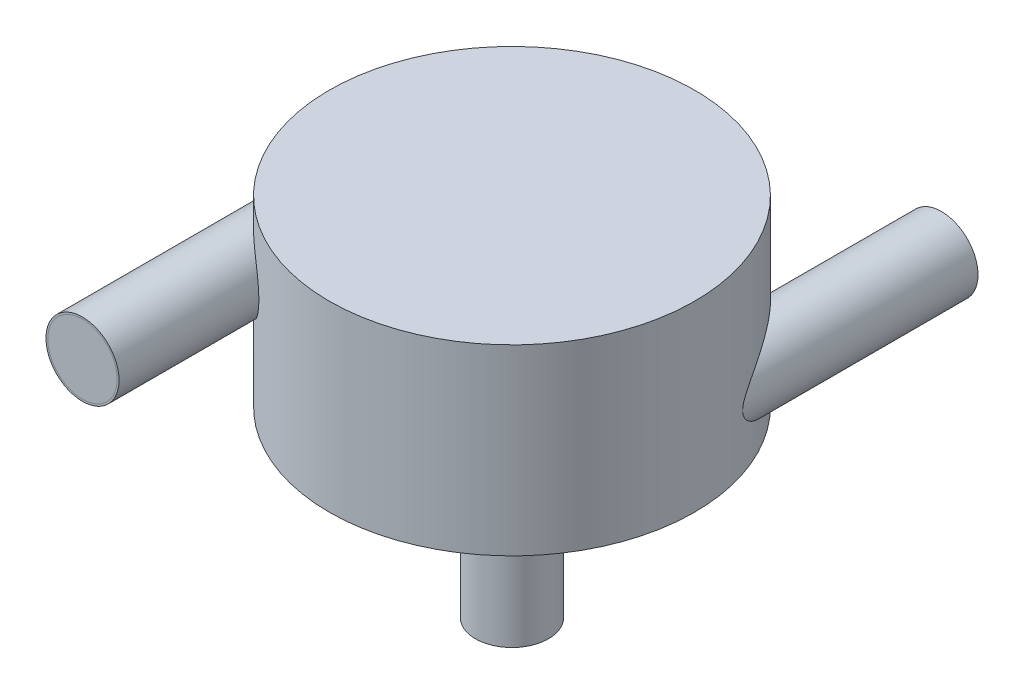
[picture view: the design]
ISO-10303-21;
HEADER;
FILE_DESCRIPTION(('STEP AP214'),'2;1');
FILE_NAME('part.step','',(''),(''),'','','');
FILE_SCHEMA(('AUTOMOTIVE_DESIGN { 1 0 10303 214 1 1 1 1 }'));
ENDSEC;
DATA;
#1=APPLICATION_CONTEXT('core data for automotive mechanical design processes');
#2=APPLICATION_PROTOCOL_DEFINITION('international standard','automotive_design',2000,#1);
#3=PRODUCT_CONTEXT('',#1,'mechanical');
#4=PRODUCT('Part','Part','',(#3));
#5=PRODUCT_RELATED_PRODUCT_CATEGORY('part','',(#4));
#6=PRODUCT_DEFINITION_FORMATION('','',#4);
#7=PRODUCT_DEFINITION_CONTEXT('part definition',#1,'design');
#8=PRODUCT_DEFINITION('design','',#6,#7);
#9=PRODUCT_DEFINITION_SHAPE('','',#8);
#10=(LENGTH_UNIT() NAMED_UNIT(*) SI_UNIT(.MILLI.,.METRE.));
#11=(NAMED_UNIT(*) PLANE_ANGLE_UNIT() SI_UNIT($,.RADIAN.));
#12=(NAMED_UNIT(*) SI_UNIT($,.STERADIAN.) SOLID_ANGLE_UNIT());
#13=UNCERTAINTY_MEASURE_WITH_UNIT(LENGTH_MEASURE(1.E-05),#10,'distance_accuracy_value','');
#14=(GEOMETRIC_REPRESENTATION_CONTEXT(3) GLOBAL_UNCERTAINTY_ASSIGNED_CONTEXT((#13)) GLOBAL_UNIT_ASSIGNED_CONTEXT((#10,
#11,#12)) REPRESENTATION_CONTEXT('',''));
#15=CARTESIAN_POINT('',(0.,0.,0.));
#16=DIRECTION('',(0.,0.,1.));
#17=DIRECTION('',(1.,0.,0.));
#18=AXIS2_PLACEMENT_3D('',#15,#16,#17);
#19=CARTESIAN_POINT('',(0.,-950.,0.));
#20=DIRECTION('',(0.,-1.,0.));
#21=DIRECTION('',(0.,0.,-1.));
#22=AXIS2_PLACEMENT_3D('',#19,#20,#21);
#23=CYLINDRICAL_SURFACE('',#22,190.);
#24=CARTESIAN_POINT('',(0.,-950.,0.));
#25=DIRECTION('',(0.,-1.,0.));
#26=DIRECTION('',(0.,0.,-1.));
#27=AXIS2_PLACEMENT_3D('',#24,#25,#26);
#28=CIRCLE('',#27,190.);
#29=CARTESIAN_POINT('',(0.,-950.,-190.));
#30=VERTEX_POINT('',#29);
#31=EDGE_CURVE('E11',#30,#30,#28,.T.);
#32=ORIENTED_EDGE('',*,*,#31,.T.);
#33=EDGE_LOOP('',(#32));
#34=FACE_BOUND('',#33,.T.);
#35=CARTESIAN_POINT('',(0.,-1000.,0.));
#36=DIRECTION('',(0.,-1.,0.));
#37=DIRECTION('',(0.,0.,-1.));
#38=AXIS2_PLACEMENT_3D('',#35,#36,#37);
#39=CIRCLE('',#38,190.);
#40=CARTESIAN_POINT('',(0.,-1000.,-190.));
#41=VERTEX_POINT('',#40);
#42=EDGE_CURVE('E63',#41,#41,#39,.T.);
#43=ORIENTED_EDGE('',*,*,#42,.F.);
#44=EDGE_LOOP('',(#43));
#45=FACE_BOUND('',#44,.T.);
#46=ADVANCED_FACE('F60',(#34,#45),#23,.T.);
#47=CARTESIAN_POINT('',(0.,-950.,0.));
#48=DIRECTION('',(0.,-1.,0.));
#49=DIRECTION('',(0.,0.,-1.));
#50=AXIS2_PLACEMENT_3D('',#47,#48,#49);
#51=PLANE('',#50);
#52=ORIENTED_EDGE('',*,*,#31,.F.);
#53=EDGE_LOOP('',(#52));
#54=FACE_BOUND('',#53,.T.);
#55=ADVANCED_FACE('F75',(#54),#51,.F.);
#56=CARTESIAN_POINT('',(0.,-1000.,0.));
#57=DIRECTION('',(0.,-1.,0.));
#58=DIRECTION('',(0.,0.,-1.));
#59=AXIS2_PLACEMENT_3D('',#56,#57,#58);
#60=PLANE('',#59);
#61=ORIENTED_EDGE('',*,*,#42,.T.);
#62=EDGE_LOOP('',(#61));
#63=FACE_BOUND('',#62,.T.);
#64=ADVANCED_FACE('F72',(#63),#60,.T.);
#65=CLOSED_SHELL('',(#46,#55,#64));
#66=MANIFOLD_SOLID_BREP('B2',#65);
#67=CARTESIAN_POINT('',(750.,300.,-1550.));
#68=DIRECTION('',(0.,0.,-1.));
#69=DIRECTION('',(-1.,0.,0.));
#70=AXIS2_PLACEMENT_3D('',#67,#68,#69);
#71=CYLINDRICAL_SURFACE('',#70,190.);
#72=CARTESIAN_POINT('',(750.,300.,-1550.));
#73=DIRECTION('',(0.,0.,-1.));
#74=DIRECTION('',(-1.,0.,0.));
#75=AXIS2_PLACEMENT_3D('',#72,#73,#74);
#76=CIRCLE('',#75,190.);
#77=CARTESIAN_POINT('',(560.,300.,-1550.));
#78=VERTEX_POINT('',#77);
#79=EDGE_CURVE('E59',#78,#78,#76,.T.);
#80=ORIENTED_EDGE('',*,*,#79,.T.);
#81=EDGE_LOOP('',(#80));
#82=FACE_BOUND('',#81,.T.);
#83=CARTESIAN_POINT('',(750.,300.,-1600.));
#84=DIRECTION('',(0.,0.,-1.));
#85=DIRECTION('',(-1.,0.,0.));
#86=AXIS2_PLACEMENT_3D('',#83,#84,#85);
#87=CIRCLE('',#86,190.);
#88=CARTESIAN_POINT('',(560.,300.,-1600.));
#89=VERTEX_POINT('',#88);
#90=EDGE_CURVE('E110',#89,#89,#87,.T.);
#91=ORIENTED_EDGE('',*,*,#90,.F.);
#92=EDGE_LOOP('',(#91));
#93=FACE_BOUND('',#92,.T.);
#94=ADVANCED_FACE('F107',(#82,#93),#71,.T.);
#95=CARTESIAN_POINT('',(750.,300.,-1550.));
#96=DIRECTION('',(0.,0.,-1.));
#97=DIRECTION('',(-1.,0.,0.));
#98=AXIS2_PLACEMENT_3D('',#95,#96,#97);
#99=PLANE('',#98);
#100=ORIENTED_EDGE('',*,*,#79,.F.);
#101=EDGE_LOOP('',(#100));
#102=FACE_BOUND('',#101,.T.);
#103=ADVANCED_FACE('F122',(#102),#99,.F.);
#104=CARTESIAN_POINT('',(750.,300.,-1600.));
#105=DIRECTION('',(0.,0.,-1.));
#106=DIRECTION('',(-1.,0.,0.));
#107=AXIS2_PLACEMENT_3D('',#104,#105,#106);
#108=PLANE('',#107);
#109=ORIENTED_EDGE('',*,*,#90,.T.);
#110=EDGE_LOOP('',(#109));
#111=FACE_BOUND('',#110,.T.);
#112=ADVANCED_FACE('F119',(#111),#108,.T.);
#113=CLOSED_SHELL('',(#94,#103,#112));
#114=MANIFOLD_SOLID_BREP('B6',#113);
#115=CARTESIAN_POINT('',(-750.,650.,1550.));
#116=DIRECTION('',(0.,0.,1.));
#117=DIRECTION('',(1.,0.,0.));
#118=AXIS2_PLACEMENT_3D('',#115,#116,#117);
#119=CYLINDRICAL_SURFACE('',#118,190.);
#120=CARTESIAN_POINT('',(-750.,650.,1550.));
#121=DIRECTION('',(0.,0.,1.));
#122=DIRECTION('',(1.,0.,0.));
#123=AXIS2_PLACEMENT_3D('',#120,#121,#122);
#124=CIRCLE('',#123,190.);
#125=CARTESIAN_POINT('',(-560.,650.,1550.));
#126=VERTEX_POINT('',#125);
#127=EDGE_CURVE('E106',#126,#126,#124,.T.);
#128=ORIENTED_EDGE('',*,*,#127,.T.);
#129=EDGE_LOOP('',(#128));
#130=FACE_BOUND('',#129,.T.);
#131=CARTESIAN_POINT('',(-750.,650.,1600.));
#132=DIRECTION('',(0.,0.,1.));
#133=DIRECTION('',(1.,0.,0.));
#134=AXIS2_PLACEMENT_3D('',#131,#132,#133);
#135=CIRCLE('',#134,190.);
#136=CARTESIAN_POINT('',(-560.,650.,1600.));
#137=VERTEX_POINT('',#136);
#138=EDGE_CURVE('E156',#137,#137,#135,.T.);
#139=ORIENTED_EDGE('',*,*,#138,.F.);
#140=EDGE_LOOP('',(#139));
#141=FACE_BOUND('',#140,.T.);
#142=ADVANCED_FACE('F153',(#130,#141),#119,.T.);
#143=CARTESIAN_POINT('',(-750.,650.,1550.));
#144=DIRECTION('',(0.,0.,1.));
#145=DIRECTION('',(1.,0.,0.));
#146=AXIS2_PLACEMENT_3D('',#143,#144,#145);
#147=PLANE('',#146);
#148=ORIENTED_EDGE('',*,*,#127,.F.);
#149=EDGE_LOOP('',(#148));
#150=FACE_BOUND('',#149,.T.);
#151=ADVANCED_FACE('F168',(#150),#147,.F.);
#152=CARTESIAN_POINT('',(-750.,650.,1600.));
#153=DIRECTION('',(0.,0.,1.));
#154=DIRECTION('',(1.,0.,0.));
#155=AXIS2_PLACEMENT_3D('',#152,#153,#154);
#156=PLANE('',#155);
#157=ORIENTED_EDGE('',*,*,#138,.T.);
#158=EDGE_LOOP('',(#157));
#159=FACE_BOUND('',#158,.T.);
#160=ADVANCED_FACE('F165',(#159),#156,.T.);
#161=CLOSED_SHELL('',(#142,#151,#160));
#162=MANIFOLD_SOLID_BREP('B54',#161);
#163=CARTESIAN_POINT('',(0.,1000.,0.));
#164=DIRECTION('',(0.,-1.,0.));
#165=DIRECTION('',(0.,0.,-1.));
#166=AXIS2_PLACEMENT_3D('',#163,#164,#165);
#167=CYLINDRICAL_SURFACE('',#166,1000.);
#168=CARTESIAN_POINT('',(-550.,650.,835.164654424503));
#169=CARTESIAN_POINT('',(-549.999999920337,652.438202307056,835.164654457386));
#170=CARTESIAN_POINT('',(-550.044599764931,654.876402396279,835.135288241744));
#171=CARTESIAN_POINT('',(-550.222835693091,659.748126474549,835.017869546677));
#172=CARTESIAN_POINT('',(-550.356471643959,662.181650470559,834.929817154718));
#173=CARTESIAN_POINT('',(-550.712289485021,667.039346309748,834.695165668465));
#174=CARTESIAN_POINT('',(-550.934470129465,669.463518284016,834.548567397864));
#175=CARTESIAN_POINT('',(-551.466569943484,674.297960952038,834.197053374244));
#176=CARTESIAN_POINT('',(-551.776489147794,676.708231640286,833.992137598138));
#177=CARTESIAN_POINT('',(-552.482958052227,681.510449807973,833.524301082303));
#178=CARTESIAN_POINT('',(-552.879510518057,683.902396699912,833.261378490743));
#179=CARTESIAN_POINT('',(-553.757820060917,688.663506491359,832.677941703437));
#180=CARTESIAN_POINT('',(-554.239577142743,691.032669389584,832.357427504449));
#181=CARTESIAN_POINT('',(-555.286588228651,695.743966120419,831.659305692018));
#182=CARTESIAN_POINT('',(-555.851842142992,698.086099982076,831.281698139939));
#183=CARTESIAN_POINT('',(-557.063869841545,702.739263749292,830.469973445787));
#184=CARTESIAN_POINT('',(-557.710643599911,705.050293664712,830.03585632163));
#185=CARTESIAN_POINT('',(-559.081828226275,709.631833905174,829.112893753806));
#186=CARTESIAN_POINT('',(-559.806048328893,711.902428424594,828.624182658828));
#187=CARTESIAN_POINT('',(-561.330956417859,716.40513498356,827.591931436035));
#188=CARTESIAN_POINT('',(-562.131644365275,718.637247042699,827.048391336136));
#189=CARTESIAN_POINT('',(-563.806827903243,723.059518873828,825.907311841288));
#190=CARTESIAN_POINT('',(-564.681322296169,725.249679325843,825.309773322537));
#191=CARTESIAN_POINT('',(-566.50130203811,729.584888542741,824.061582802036));
#192=CARTESIAN_POINT('',(-567.44678743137,731.729937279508,823.410930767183));
#193=CARTESIAN_POINT('',(-569.405774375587,735.971995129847,822.057468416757));
#194=CARTESIAN_POINT('',(-570.419276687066,738.069003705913,821.354657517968));
#195=CARTESIAN_POINT('',(-572.511169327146,742.212258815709,819.897911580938));
#196=CARTESIAN_POINT('',(-573.589559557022,744.258505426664,819.143976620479));
#197=CARTESIAN_POINT('',(-575.80802247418,748.297835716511,817.586055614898));
#198=CARTESIAN_POINT('',(-576.948095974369,750.290918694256,816.782068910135));
#199=CARTESIAN_POINT('',(-579.286625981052,754.221754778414,815.12517960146));
#200=CARTESIAN_POINT('',(-580.48508349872,756.15950692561,814.272276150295));
#201=CARTESIAN_POINT('',(-582.988199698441,760.057462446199,812.482137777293));
#202=CARTESIAN_POINT('',(-584.295203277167,762.015225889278,811.542868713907));
#203=CARTESIAN_POINT('',(-586.965081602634,765.866760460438,809.613923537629));
#204=CARTESIAN_POINT('',(-588.327956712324,767.760531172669,808.624247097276));
#205=CARTESIAN_POINT('',(-591.105700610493,771.482483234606,806.595938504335));
#206=CARTESIAN_POINT('',(-592.520568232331,773.310666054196,805.557307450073));
#207=CARTESIAN_POINT('',(-595.398513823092,776.900246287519,803.432516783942));
#208=CARTESIAN_POINT('',(-596.861592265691,778.661643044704,802.34635670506));
#209=CARTESIAN_POINT('',(-599.832565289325,782.117125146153,800.12769714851));
#210=CARTESIAN_POINT('',(-601.340471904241,783.811192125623,798.995185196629));
#211=CARTESIAN_POINT('',(-604.39697994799,787.130780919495,796.68560907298));
#212=CARTESIAN_POINT('',(-605.945580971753,788.756303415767,795.508545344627));
#213=CARTESIAN_POINT('',(-609.080025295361,791.938539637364,793.111225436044));
#214=CARTESIAN_POINT('',(-610.665872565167,793.495245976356,791.890964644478));
#215=CARTESIAN_POINT('',(-613.871116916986,796.539458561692,789.408868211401));
#216=CARTESIAN_POINT('',(-615.490515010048,798.026962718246,788.147031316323));
#217=CARTESIAN_POINT('',(-619.400746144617,801.502822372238,785.080299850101));
#218=CARTESIAN_POINT('',(-621.705747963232,803.458723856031,783.25656771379));
#219=CARTESIAN_POINT('',(-626.365304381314,807.236955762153,779.535372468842));
#220=CARTESIAN_POINT('',(-628.719862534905,809.059276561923,777.637904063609));
#221=CARTESIAN_POINT('',(-633.470632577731,812.571939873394,773.772793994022));
#222=CARTESIAN_POINT('',(-635.866854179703,814.262251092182,771.805135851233));
#223=CARTESIAN_POINT('',(-640.692508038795,817.512192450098,767.803968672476));
#224=CARTESIAN_POINT('',(-643.121939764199,819.071824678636,765.770460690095));
#225=CARTESIAN_POINT('',(-648.010265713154,822.064869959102,761.638334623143));
#226=CARTESIAN_POINT('',(-650.46919716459,823.49809895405,759.53962741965));
#227=CARTESIAN_POINT('',(-655.406311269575,826.238490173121,755.283516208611));
#228=CARTESIAN_POINT('',(-657.884493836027,827.545652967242,753.126112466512));
#229=CARTESIAN_POINT('',(-662.853900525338,830.036892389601,748.756071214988));
#230=CARTESIAN_POINT('',(-665.345124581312,831.220969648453,746.543433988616));
#231=CARTESIAN_POINT('',(-670.335001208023,833.469281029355,742.066186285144));
#232=CARTESIAN_POINT('',(-672.833654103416,834.533509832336,739.801573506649));
#233=CARTESIAN_POINT('',(-678.711642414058,836.898983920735,734.419144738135));
#234=CARTESIAN_POINT('',(-682.091934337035,838.152117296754,731.281132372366));
#235=CARTESIAN_POINT('',(-688.845202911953,840.454244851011,724.923305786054));
#236=CARTESIAN_POINT('',(-692.218178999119,841.503223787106,721.703485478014));
#237=CARTESIAN_POINT('',(-698.94767166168,843.406022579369,715.188151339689));
#238=CARTESIAN_POINT('',(-702.304183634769,844.259790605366,711.892617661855));
#239=CARTESIAN_POINT('',(-708.991205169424,845.780581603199,705.233109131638));
#240=CARTESIAN_POINT('',(-712.321715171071,846.447607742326,701.869135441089));
#241=CARTESIAN_POINT('',(-718.952727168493,847.604162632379,695.07519799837));
#242=CARTESIAN_POINT('',(-722.253196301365,848.093515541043,691.645172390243));
#243=CARTESIAN_POINT('',(-728.814476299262,848.902236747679,684.727818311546));
#244=CARTESIAN_POINT('',(-732.075287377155,849.221605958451,681.240490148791));
#245=CARTESIAN_POINT('',(-738.551844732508,849.698479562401,674.213617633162));
#246=CARTESIAN_POINT('',(-741.767592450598,849.855989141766,670.674074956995));
#247=CARTESIAN_POINT('',(-748.149682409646,850.016913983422,663.547238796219));
#248=CARTESIAN_POINT('',(-751.316022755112,850.020323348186,659.959943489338));
#249=CARTESIAN_POINT('',(-758.948619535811,849.850243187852,651.186483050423));
#250=CARTESIAN_POINT('',(-763.387073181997,849.599891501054,645.977463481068));
#251=CARTESIAN_POINT('',(-772.146142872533,848.81872071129,635.481760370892));
#252=CARTESIAN_POINT('',(-776.466748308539,848.287876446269,630.195069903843));
#253=CARTESIAN_POINT('',(-784.984759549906,846.963577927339,619.552580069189));
#254=CARTESIAN_POINT('',(-789.182117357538,846.170022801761,614.1967549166));
#255=CARTESIAN_POINT('',(-797.446674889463,844.336638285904,603.427602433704));
#256=CARTESIAN_POINT('',(-801.513877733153,843.296814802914,598.014276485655));
#257=CARTESIAN_POINT('',(-809.521649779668,840.983176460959,587.128976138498));
#258=CARTESIAN_POINT('',(-813.461979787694,839.708946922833,581.656914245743));
#259=CARTESIAN_POINT('',(-821.205693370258,836.940250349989,570.671857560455));
#260=CARTESIAN_POINT('',(-825.009076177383,835.445782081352,565.158862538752));
#261=CARTESIAN_POINT('',(-832.476037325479,832.247621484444,554.101204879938));
#262=CARTESIAN_POINT('',(-836.139649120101,830.543979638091,548.556550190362));
#263=CARTESIAN_POINT('',(-843.32681673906,826.935792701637,537.441787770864));
#264=CARTESIAN_POINT('',(-846.850372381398,825.031247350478,531.871680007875));
#265=CARTESIAN_POINT('',(-852.092028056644,821.992706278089,523.403029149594));
#266=CARTESIAN_POINT('',(-853.861831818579,820.929723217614,520.51072482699));
#267=CARTESIAN_POINT('',(-857.363487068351,818.75228198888,514.722537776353));
#268=CARTESIAN_POINT('',(-859.095339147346,817.637824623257,511.826655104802));
#269=CARTESIAN_POINT('',(-862.521047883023,815.357936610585,506.032380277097));
#270=CARTESIAN_POINT('',(-864.214903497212,814.192504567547,503.133988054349));
#271=CARTESIAN_POINT('',(-867.564464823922,811.811060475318,497.336011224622));
#272=CARTESIAN_POINT('',(-869.220171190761,810.595049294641,494.436426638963));
#273=CARTESIAN_POINT('',(-872.494184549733,808.111979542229,488.635850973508));
#274=CARTESIAN_POINT('',(-874.112472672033,806.844896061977,485.734859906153));
#275=CARTESIAN_POINT('',(-877.31071108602,804.260203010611,479.934250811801));
#276=CARTESIAN_POINT('',(-878.890661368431,802.942593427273,477.034632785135));
#277=CARTESIAN_POINT('',(-882.012088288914,800.256607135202,471.238274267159));
#278=CARTESIAN_POINT('',(-883.553565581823,798.888231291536,468.341533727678));
#279=CARTESIAN_POINT('',(-886.597942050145,796.100180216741,462.552466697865));
#280=CARTESIAN_POINT('',(-888.100841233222,794.680504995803,459.660140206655));
#281=CARTESIAN_POINT('',(-891.067849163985,791.789113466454,453.881742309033));
#282=CARTESIAN_POINT('',(-892.531959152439,790.317398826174,450.99567070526));
#283=CARTESIAN_POINT('',(-895.421230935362,787.320783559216,445.231638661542));
#284=CARTESIAN_POINT('',(-896.84639268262,785.795882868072,442.353678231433));
#285=CARTESIAN_POINT('',(-899.657614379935,782.691311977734,436.607841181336));
#286=CARTESIAN_POINT('',(-901.043671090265,781.111637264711,433.739965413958));
#287=CARTESIAN_POINT('',(-903.776211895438,777.895773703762,428.017071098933));
#288=CARTESIAN_POINT('',(-905.122696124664,776.259585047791,425.162052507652));
#289=CARTESIAN_POINT('',(-907.774402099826,772.929912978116,419.470477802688));
#290=CARTESIAN_POINT('',(-909.079661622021,771.236485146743,416.633906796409));
#291=CARTESIAN_POINT('',(-911.649699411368,767.787942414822,410.979888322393));
#292=CARTESIAN_POINT('',(-912.914477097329,766.032826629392,408.162441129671));
#293=CARTESIAN_POINT('',(-915.40256622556,762.457696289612,402.551311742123));
#294=CARTESIAN_POINT('',(-916.625885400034,760.637693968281,399.757625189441));
#295=CARTESIAN_POINT('',(-919.030310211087,756.92820029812,394.198501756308));
#296=CARTESIAN_POINT('',(-920.211417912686,755.038712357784,391.433063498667));
#297=CARTESIAN_POINT('',(-922.373853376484,751.444759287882,386.307047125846));
#298=CARTESIAN_POINT('',(-923.360640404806,749.749711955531,383.942170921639));
#299=CARTESIAN_POINT('',(-925.30069231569,746.299452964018,379.242784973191));
#300=CARTESIAN_POINT('',(-926.253958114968,744.544242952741,376.908274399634));
#301=CARTESIAN_POINT('',(-928.126152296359,740.967851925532,372.274217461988));
#302=CARTESIAN_POINT('',(-929.045063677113,739.146639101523,369.974688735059));
#303=CARTESIAN_POINT('',(-930.846388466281,735.433264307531,365.418938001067));
#304=CARTESIAN_POINT('',(-931.728802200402,733.541102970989,363.16271560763));
#305=CARTESIAN_POINT('',(-933.450478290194,729.689081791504,358.714179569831));
#306=CARTESIAN_POINT('',(-934.289942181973,727.729627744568,356.521593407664));
#307=CARTESIAN_POINT('',(-935.927965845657,723.725648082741,352.199068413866));
#308=CARTESIAN_POINT('',(-936.726522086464,721.681115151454,350.069134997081));
#309=CARTESIAN_POINT('',(-938.278221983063,717.500212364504,345.888629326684));
#310=CARTESIAN_POINT('',(-939.031411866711,715.363939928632,343.837977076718));
#311=CARTESIAN_POINT('',(-940.488402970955,710.987594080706,339.832459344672));
#312=CARTESIAN_POINT('',(-941.19221816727,708.747550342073,337.877566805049));
#313=CARTESIAN_POINT('',(-942.126054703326,705.573488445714,335.25973278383));
#314=CARTESIAN_POINT('',(-942.379900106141,704.688525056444,334.545487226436));
#315=CARTESIAN_POINT('',(-942.879043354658,702.901188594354,333.136110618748));
#316=CARTESIAN_POINT('',(-943.124341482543,701.998816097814,332.440978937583));
#317=CARTESIAN_POINT('',(-943.846723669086,699.26462409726,330.386844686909));
#318=CARTESIAN_POINT('',(-944.310341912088,697.405573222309,329.058972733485));
#319=CARTESIAN_POINT('',(-945.197741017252,693.607905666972,326.501249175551));
#320=CARTESIAN_POINT('',(-945.621466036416,691.669182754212,325.271535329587));
#321=CARTESIAN_POINT('',(-946.422939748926,687.710814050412,322.932110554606));
#322=CARTESIAN_POINT('',(-946.800686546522,685.691164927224,321.822404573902));
#323=CARTESIAN_POINT('',(-947.508974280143,681.538979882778,319.731107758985));
#324=CARTESIAN_POINT('',(-947.838719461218,679.405202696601,318.751695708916));
#325=CARTESIAN_POINT('',(-948.436434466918,675.055814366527,316.968793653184));
#326=CARTESIAN_POINT('',(-948.704405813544,672.840205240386,316.16529931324));
#327=CARTESIAN_POINT('',(-949.053519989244,669.467185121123,315.115139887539));
#328=CARTESIAN_POINT('',(-949.160974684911,668.336137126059,314.791266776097));
#329=CARTESIAN_POINT('',(-949.357556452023,666.058344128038,314.197911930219));
#330=CARTESIAN_POINT('',(-949.446686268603,664.911601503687,313.92842204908));
#331=CARTESIAN_POINT('',(-949.605744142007,662.604898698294,313.446957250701));
#332=CARTESIAN_POINT('',(-949.675674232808,661.444939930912,313.234976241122));
#333=CARTESIAN_POINT('',(-949.795607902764,659.114601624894,312.871123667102));
#334=CARTESIAN_POINT('',(-949.845612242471,657.944222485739,312.719249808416));
#335=CARTESIAN_POINT('',(-949.920993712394,655.7187087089,312.490189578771));
#336=CARTESIAN_POINT('',(-949.948393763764,654.664270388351,312.406870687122));
#337=CARTESIAN_POINT('',(-949.986502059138,652.552314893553,312.290969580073));
#338=CARTESIAN_POINT('',(-949.997210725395,651.494797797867,312.258386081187));
#339=CARTESIAN_POINT('',(-950.001833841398,649.379470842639,312.244320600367));
#340=CARTESIAN_POINT('',(-949.995749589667,648.321661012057,312.262834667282));
#341=CARTESIAN_POINT('',(-949.966848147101,646.208383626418,312.350747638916));
#342=CARTESIAN_POINT('',(-949.944030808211,645.152916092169,312.42014699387));
#343=CARTESIAN_POINT('',(-949.88184538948,643.045866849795,312.609164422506));
#344=CARTESIAN_POINT('',(-949.842459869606,641.994290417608,312.728835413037));
#345=CARTESIAN_POINT('',(-949.747490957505,639.898495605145,313.017134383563));
#346=CARTESIAN_POINT('',(-949.69190557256,638.854278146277,313.185768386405));
#347=CARTESIAN_POINT('',(-949.565024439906,636.775579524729,313.570255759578));
#348=CARTESIAN_POINT('',(-949.493729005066,635.74109816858,313.786108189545));
#349=CARTESIAN_POINT('',(-949.336001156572,633.683644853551,314.262978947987));
#350=CARTESIAN_POINT('',(-949.249566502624,632.660674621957,314.52400396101));
#351=CARTESIAN_POINT('',(-949.050760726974,630.503678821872,315.123412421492));
#352=CARTESIAN_POINT('',(-948.936510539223,629.371368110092,315.467352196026));
#353=CARTESIAN_POINT('',(-948.690758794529,627.125129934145,316.20562227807));
#354=CARTESIAN_POINT('',(-948.559254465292,626.011205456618,316.599960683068));
#355=CARTESIAN_POINT('',(-948.140390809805,622.699157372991,317.853070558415));
#356=CARTESIAN_POINT('',(-947.82864230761,620.530348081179,318.782053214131));
#357=CARTESIAN_POINT('',(-947.147752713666,616.27434035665,320.799421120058));
#358=CARTESIAN_POINT('',(-946.778518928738,614.187280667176,321.888063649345));
#359=CARTESIAN_POINT('',(-945.990178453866,610.097791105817,324.197579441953));
#360=CARTESIAN_POINT('',(-945.571069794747,608.095364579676,325.418457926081));
#361=CARTESIAN_POINT('',(-944.731532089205,604.360839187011,327.847253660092));
#362=CARTESIAN_POINT('',(-944.315102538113,602.621257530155,329.045135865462));
#363=CARTESIAN_POINT('',(-943.450167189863,599.204939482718,331.516962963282));
#364=CARTESIAN_POINT('',(-943.001655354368,597.528215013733,332.790922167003));
#365=CARTESIAN_POINT('',(-942.075406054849,594.232897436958,335.404013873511));
#366=CARTESIAN_POINT('',(-941.597648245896,592.614346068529,336.743191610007));
#367=CARTESIAN_POINT('',(-940.615759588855,589.432651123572,339.476216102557));
#368=CARTESIAN_POINT('',(-940.111630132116,587.869504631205,340.870059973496));
#369=CARTESIAN_POINT('',(-939.077646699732,584.79042958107,343.708395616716));
#370=CARTESIAN_POINT('',(-938.547726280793,583.274641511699,345.153015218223));
#371=CARTESIAN_POINT('',(-937.465152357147,580.291069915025,348.082643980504));
#372=CARTESIAN_POINT('',(-936.912498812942,578.823286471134,349.56765321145));
#373=CARTESIAN_POINT('',(-935.786071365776,575.932864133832,352.571980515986));
#374=CARTESIAN_POINT('',(-935.21230525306,574.510208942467,354.091285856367));
#375=CARTESIAN_POINT('',(-934.044608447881,571.706398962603,357.160139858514));
#376=CARTESIAN_POINT('',(-933.45067723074,570.325245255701,358.709689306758));
#377=CARTESIAN_POINT('',(-931.988552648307,567.026156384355,362.495537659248));
#378=CARTESIAN_POINT('',(-931.110526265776,565.128037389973,364.745322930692));
#379=CARTESIAN_POINT('',(-929.317781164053,561.403131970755,369.289085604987));
#380=CARTESIAN_POINT('',(-928.403059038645,559.576352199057,371.583067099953));
#381=CARTESIAN_POINT('',(-926.538353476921,555.987768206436,376.208585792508));
#382=CARTESIAN_POINT('',(-925.5883577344,554.225987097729,378.540135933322));
#383=CARTESIAN_POINT('',(-923.65477106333,550.763149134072,383.234010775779));
#384=CARTESIAN_POINT('',(-922.671181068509,549.062090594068,385.596334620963));
#385=CARTESIAN_POINT('',(-920.669899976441,545.713880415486,390.350608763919));
#386=CARTESIAN_POINT('',(-919.652159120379,544.06681502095,392.742598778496));
#387=CARTESIAN_POINT('',(-917.584829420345,540.825738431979,397.548643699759));
#388=CARTESIAN_POINT('',(-916.535240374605,539.231727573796,399.962698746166));
#389=CARTESIAN_POINT('',(-914.405054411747,536.094016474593,404.809093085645));
#390=CARTESIAN_POINT('',(-913.324462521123,534.55030816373,407.24142936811));
#391=CARTESIAN_POINT('',(-911.132640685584,531.510408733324,412.121907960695));
#392=CARTESIAN_POINT('',(-910.021410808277,530.014217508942,414.570050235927));
#393=CARTESIAN_POINT('',(-907.764325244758,527.061460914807,419.489310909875));
#394=CARTESIAN_POINT('',(-906.618351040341,525.605073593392,421.96048173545));
#395=CARTESIAN_POINT('',(-904.296293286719,522.736260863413,426.914156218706));
#396=CARTESIAN_POINT('',(-903.120209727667,521.323835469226,429.396659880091));
#397=CARTESIAN_POINT('',(-900.738186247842,518.541439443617,434.371183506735));
#398=CARTESIAN_POINT('',(-899.532245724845,517.171469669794,436.863203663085));
#399=CARTESIAN_POINT('',(-897.090753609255,514.472803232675,441.855066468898));
#400=CARTESIAN_POINT('',(-895.855202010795,513.144106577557,444.354909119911));
#401=CARTESIAN_POINT('',(-893.355618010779,510.528005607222,449.359050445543));
#402=CARTESIAN_POINT('',(-892.09160798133,509.240570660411,451.863344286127));
#403=CARTESIAN_POINT('',(-889.534324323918,506.705148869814,456.877013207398));
#404=CARTESIAN_POINT('',(-888.241050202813,505.457162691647,459.386388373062));
#405=CARTESIAN_POINT('',(-885.625368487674,503.000070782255,464.409004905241));
#406=CARTESIAN_POINT('',(-884.302960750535,501.790965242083,466.922246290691));
#407=CARTESIAN_POINT('',(-881.629112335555,499.411222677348,471.951500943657));
#408=CARTESIAN_POINT('',(-880.277671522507,498.240585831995,474.467514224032));
#409=CARTESIAN_POINT('',(-877.147516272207,495.601702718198,480.235270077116));
#410=CARTESIAN_POINT('',(-875.359124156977,494.146215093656,483.487610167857));
#411=CARTESIAN_POINT('',(-871.734175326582,491.298700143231,489.993259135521));
#412=CARTESIAN_POINT('',(-869.897618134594,489.906673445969,493.246568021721));
#413=CARTESIAN_POINT('',(-866.17639319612,487.186124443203,499.752438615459));
#414=CARTESIAN_POINT('',(-864.291723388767,485.857604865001,503.005000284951));
#415=CARTESIAN_POINT('',(-860.47447498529,483.264538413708,509.507498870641));
#416=CARTESIAN_POINT('',(-858.541896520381,481.999991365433,512.757435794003));
#417=CARTESIAN_POINT('',(-854.627864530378,479.534865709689,519.254855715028));
#418=CARTESIAN_POINT('',(-852.646384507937,478.334322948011,522.502336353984));
#419=CARTESIAN_POINT('',(-848.635719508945,475.998908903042,528.991459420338));
#420=CARTESIAN_POINT('',(-846.606534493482,474.86403767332,532.233101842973));
#421=CARTESIAN_POINT('',(-842.500668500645,472.661189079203,538.70893990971));
#422=CARTESIAN_POINT('',(-840.423988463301,471.593210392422,541.943135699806));
#423=CARTESIAN_POINT('',(-836.22329922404,469.525561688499,548.402622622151));
#424=CARTESIAN_POINT('',(-834.099290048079,468.525891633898,551.627913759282));
#425=CARTESIAN_POINT('',(-829.812023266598,466.600045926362,558.056339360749));
#426=CARTESIAN_POINT('',(-827.648936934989,465.673615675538,561.259511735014));
#427=CARTESIAN_POINT('',(-823.276340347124,463.892097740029,567.654005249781));
#428=CARTESIAN_POINT('',(-821.066830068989,463.03701008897,570.845326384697));
#429=CARTESIAN_POINT('',(-816.601674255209,461.400234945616,577.214719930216));
#430=CARTESIAN_POINT('',(-814.346026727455,460.618550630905,580.39279176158));
#431=CARTESIAN_POINT('',(-809.789164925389,459.130934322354,586.733970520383));
#432=CARTESIAN_POINT('',(-807.487950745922,458.425002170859,589.897077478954));
#433=CARTESIAN_POINT('',(-802.841963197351,457.091825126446,596.204759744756));
#434=CARTESIAN_POINT('',(-800.497217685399,456.464531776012,599.349345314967));
#435=CARTESIAN_POINT('',(-795.763458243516,455.290851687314,605.620303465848));
#436=CARTESIAN_POINT('',(-793.37444396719,454.744465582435,608.746675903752));
#437=CARTESIAN_POINT('',(-788.553252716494,453.735608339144,614.97909503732));
#438=CARTESIAN_POINT('',(-786.121080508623,453.273127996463,618.085143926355));
#439=CARTESIAN_POINT('',(-781.214398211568,452.435186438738,624.27530986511));
#440=CARTESIAN_POINT('',(-778.739889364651,452.05972267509,627.359427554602));
#441=CARTESIAN_POINT('',(-773.173708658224,451.322935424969,634.213011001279));
#442=CARTESIAN_POINT('',(-770.071401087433,450.984873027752,637.976379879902));
#443=CARTESIAN_POINT('',(-763.807056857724,450.452396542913,645.463091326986));
#444=CARTESIAN_POINT('',(-760.645023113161,450.257975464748,649.186435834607));
#445=CARTESIAN_POINT('',(-754.264241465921,450.019978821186,656.58916513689));
#446=CARTESIAN_POINT('',(-751.045493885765,449.976402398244,660.26855018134));
#447=CARTESIAN_POINT('',(-744.555061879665,450.047792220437,667.578947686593));
#448=CARTESIAN_POINT('',(-741.28337694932,450.162759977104,671.209959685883));
#449=CARTESIAN_POINT('',(-734.693665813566,450.559269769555,678.416569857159));
#450=CARTESIAN_POINT('',(-731.375668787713,450.840711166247,681.992200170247));
#451=CARTESIAN_POINT('',(-724.696794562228,451.578641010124,689.085106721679));
#452=CARTESIAN_POINT('',(-721.33591688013,452.035131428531,692.602382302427));
#453=CARTESIAN_POINT('',(-714.578382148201,453.131963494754,699.572220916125));
#454=CARTESIAN_POINT('',(-711.181731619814,453.772272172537,703.024795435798));
#455=CARTESIAN_POINT('',(-704.359731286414,455.245943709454,709.859618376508));
#456=CARTESIAN_POINT('',(-700.934383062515,456.079295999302,713.241870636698));
#457=CARTESIAN_POINT('',(-694.834755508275,457.73866699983,719.179040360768));
#458=CARTESIAN_POINT('',(-692.164403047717,458.524375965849,721.749312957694));
#459=CARTESIAN_POINT('',(-686.81649822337,460.221931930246,726.840233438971));
#460=CARTESIAN_POINT('',(-684.138946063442,461.133775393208,729.360882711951));
#461=CARTESIAN_POINT('',(-678.781891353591,463.087961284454,734.349058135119));
#462=CARTESIAN_POINT('',(-676.102388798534,464.130304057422,736.816584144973));
#463=CARTESIAN_POINT('',(-670.747320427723,466.349752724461,741.694782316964));
#464=CARTESIAN_POINT('',(-668.071754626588,467.526859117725,744.105454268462));
#465=CARTESIAN_POINT('',(-662.734067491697,470.018550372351,748.863354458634));
#466=CARTESIAN_POINT('',(-660.071934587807,471.332982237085,751.210649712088));
#467=CARTESIAN_POINT('',(-654.765316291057,474.104249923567,755.84044554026));
#468=CARTESIAN_POINT('',(-652.12083110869,475.561087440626,758.122945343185));
#469=CARTESIAN_POINT('',(-646.857916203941,478.620382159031,762.618391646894));
#470=CARTESIAN_POINT('',(-644.239482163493,480.222814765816,764.83134981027));
#471=CARTESIAN_POINT('',(-639.036932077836,483.57651989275,769.183527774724));
#472=CARTESIAN_POINT('',(-636.452814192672,485.327784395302,771.32275153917));
#473=CARTESIAN_POINT('',(-631.865089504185,488.598848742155,775.082814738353));
#474=CARTESIAN_POINT('',(-629.853275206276,490.090284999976,776.718370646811));
#475=CARTESIAN_POINT('',(-625.86188780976,493.168624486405,779.938119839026));
#476=CARTESIAN_POINT('',(-623.882313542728,494.755524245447,781.522314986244));
#477=CARTESIAN_POINT('',(-619.96072072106,498.02532123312,784.636842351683));
#478=CARTESIAN_POINT('',(-618.018699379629,499.708211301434,786.167178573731));
#479=CARTESIAN_POINT('',(-614.177500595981,503.170391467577,789.17168172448));
#480=CARTESIAN_POINT('',(-612.27832350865,504.949682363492,790.64584818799));
#481=CARTESIAN_POINT('',(-608.528466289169,508.604596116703,793.53557512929));
#482=CARTESIAN_POINT('',(-606.677787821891,510.480222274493,794.951133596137));
#483=CARTESIAN_POINT('',(-603.030905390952,514.327195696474,797.721110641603));
#484=CARTESIAN_POINT('',(-601.23470127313,516.298542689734,799.075529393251));
#485=CARTESIAN_POINT('',(-597.702770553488,520.33601893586,801.720815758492));
#486=CARTESIAN_POINT('',(-595.967046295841,522.402151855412,803.011680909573));
#487=CARTESIAN_POINT('',(-592.56235444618,526.627599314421,805.527365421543));
#488=CARTESIAN_POINT('',(-590.893386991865,528.786914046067,806.752184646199));
#489=CARTESIAN_POINT('',(-587.614777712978,533.215186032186,809.143389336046));
#490=CARTESIAN_POINT('',(-586.005752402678,535.484912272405,810.309197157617));
#491=CARTESIAN_POINT('',(-582.868461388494,540.114299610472,812.568824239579));
#492=CARTESIAN_POINT('',(-581.340195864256,542.473960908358,813.662643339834));
#493=CARTESIAN_POINT('',(-578.370773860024,547.280050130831,815.776053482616));
#494=CARTESIAN_POINT('',(-576.929623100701,549.726483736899,816.795639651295));
#495=CARTESIAN_POINT('',(-574.140888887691,554.702014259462,818.758296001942));
#496=CARTESIAN_POINT('',(-572.793305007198,557.231110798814,819.701366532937));
#497=CARTESIAN_POINT('',(-570.198888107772,562.365380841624,821.508201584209));
#498=CARTESIAN_POINT('',(-568.95197656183,564.970492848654,822.372027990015));
#499=CARTESIAN_POINT('',(-566.56361135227,570.253558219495,824.019283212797));
#500=CARTESIAN_POINT('',(-565.422159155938,572.931512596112,824.802710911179));
#501=CARTESIAN_POINT('',(-563.250522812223,578.353918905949,826.28722515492));
#502=CARTESIAN_POINT('',(-562.220317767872,581.098358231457,826.98832716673));
#503=CARTESIAN_POINT('',(-560.276146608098,586.647792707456,828.30671827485));
#504=CARTESIAN_POINT('',(-559.36217410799,589.452784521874,828.9240119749));
#505=CARTESIAN_POINT('',(-557.813112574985,594.592319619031,829.967007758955));
#506=CARTESIAN_POINT('',(-557.157713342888,596.917870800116,830.40702584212));
#507=CARTESIAN_POINT('',(-555.929487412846,601.60067384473,831.229782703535));
#508=CARTESIAN_POINT('',(-555.356658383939,603.957924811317,831.612523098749));
#509=CARTESIAN_POINT('',(-554.295668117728,608.699681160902,832.320081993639));
#510=CARTESIAN_POINT('',(-553.807495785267,611.084182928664,832.644908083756));
#511=CARTESIAN_POINT('',(-552.917470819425,615.876457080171,833.236194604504));
#512=CARTESIAN_POINT('',(-552.515619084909,618.284229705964,833.502654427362));
#513=CARTESIAN_POINT('',(-551.799822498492,623.11773081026,833.976702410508));
#514=CARTESIAN_POINT('',(-551.485847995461,625.543452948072,834.184310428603));
#515=CARTESIAN_POINT('',(-550.946774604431,630.409067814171,834.540445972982));
#516=CARTESIAN_POINT('',(-550.721675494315,632.848960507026,834.688973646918));
#517=CARTESIAN_POINT('',(-550.361174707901,637.73832800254,834.926717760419));
#518=CARTESIAN_POINT('',(-550.225775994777,640.187803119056,835.015932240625));
#519=CARTESIAN_POINT('',(-550.045188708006,645.091519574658,835.134900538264));
#520=CARTESIAN_POINT('',(-550.000000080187,647.54576091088,835.164654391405));
#521=CARTESIAN_POINT('',(-550.,650.,835.164654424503));
#522=B_SPLINE_CURVE_WITH_KNOTS('',3,(#168,#169,#170,#171,#172,#173,#174,#175,#176,#177,#178,
#179,#180,#181,#182,#183,#184,#185,#186,#187,#188,#189,#190,#191,#192,#193,#194,#195,#196,#197,
#198,#199,#200,#201,#202,#203,#204,#205,#206,#207,#208,#209,#210,#211,#212,#213,#214,#215,#216,
#217,#218,#219,#220,#221,#222,#223,#224,#225,#226,#227,#228,#229,#230,#231,#232,#233,#234,#235,
#236,#237,#238,#239,#240,#241,#242,#243,#244,#245,#246,#247,#248,#249,#250,#251,#252,#253,#254,
#255,#256,#257,#258,#259,#260,#261,#262,#263,#264,#265,#266,#267,#268,#269,#270,#271,#272,#273,
#274,#275,#276,#277,#278,#279,#280,#281,#282,#283,#284,#285,#286,#287,#288,#289,#290,#291,#292,
#293,#294,#295,#296,#297,#298,#299,#300,#301,#302,#303,#304,#305,#306,#307,#308,#309,#310,#311,
#312,#313,#314,#315,#316,#317,#318,#319,#320,#321,#322,#323,#324,#325,#326,#327,#328,#329,#330,
#331,#332,#333,#334,#335,#336,#337,#338,#339,#340,#341,#342,#343,#344,#345,#346,#347,#348,#349,
#350,#351,#352,#353,#354,#355,#356,#357,#358,#359,#360,#361,#362,#363,#364,#365,#366,#367,#368,
#369,#370,#371,#372,#373,#374,#375,#376,#377,#378,#379,#380,#381,#382,#383,#384,#385,#386,#387,
#388,#389,#390,#391,#392,#393,#394,#395,#396,#397,#398,#399,#400,#401,#402,#403,#404,#405,#406,
#407,#408,#409,#410,#411,#412,#413,#414,#415,#416,#417,#418,#419,#420,#421,#422,#423,#424,#425,
#426,#427,#428,#429,#430,#431,#432,#433,#434,#435,#436,#437,#438,#439,#440,#441,#442,#443,#444,
#445,#446,#447,#448,#449,#450,#451,#452,#453,#454,#455,#456,#457,#458,#459,#460,#461,#462,#463,
#464,#465,#466,#467,#468,#469,#470,#471,#472,#473,#474,#475,#476,#477,#478,#479,#480,#481,#482,
#483,#484,#485,#486,#487,#488,#489,#490,#491,#492,#493,#494,#495,#496,#497,#498,#499,#500,#501,
#502,#503,#504,#505,#506,#507,#508,#509,#510,#511,#512,#513,#514,#515,#516,#517,#518,#519,#520,
#521),.UNSPECIFIED.,.T.,.F.,(4,2,2,2,2,2,2,2,2,2,2,2,2,2,2,2,2,2,2,2,2,2,2,2,2,2,2,2,2,2,2,2,2,
2,2,2,2,2,2,2,2,2,2,2,2,2,2,2,2,2,2,2,2,2,2,2,2,2,2,2,2,2,2,2,2,2,2,2,2,2,2,2,2,2,2,2,2,2,2,2,2,
2,2,2,2,2,2,2,2,2,2,2,2,2,2,2,2,2,2,2,2,2,2,2,2,2,2,2,2,2,2,2,2,2,2,2,2,2,2,2,2,2,2,2,2,2,2,2,2,
2,2,2,2,2,2,2,2,2,2,2,2,2,2,2,2,2,2,2,2,2,2,2,2,2,2,2,2,2,2,2,2,2,2,2,2,2,2,2,2,2,2,2,2,2,2,2,
4),(0.,7.31401910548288,14.6280273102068,21.9419326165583,29.2558408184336,36.5699825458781,
43.8841246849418,51.1982589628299,58.5123909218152,65.8089045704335,73.1054145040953,
80.4018060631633,87.6982021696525,94.9946798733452,102.29114647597,109.587709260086,
116.884398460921,124.485705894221,132.087062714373,139.688249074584,147.289510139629,
154.892830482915,162.496075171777,170.100133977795,177.704422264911,188.292011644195,
198.880362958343,209.471216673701,220.061901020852,230.66776037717,241.273571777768,
251.879328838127,262.485556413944,276.818530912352,291.1525750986,305.49042068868,
319.828023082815,334.179776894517,348.531453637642,362.882670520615,377.234436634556,
397.770649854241,418.308705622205,438.854656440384,459.400114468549,479.982274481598,
500.564549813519,521.141867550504,541.719212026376,552.379319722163,563.039261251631,
573.699494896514,584.359545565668,595.024859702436,605.690176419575,616.355311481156,
627.020444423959,637.685235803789,648.350040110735,659.01572538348,669.681374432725,
680.336948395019,690.992675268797,701.646403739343,712.299610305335,721.515946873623,
730.732031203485,739.952617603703,749.17312170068,758.345405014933,767.518478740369,
776.68204129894,785.842999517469,789.338404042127,792.833693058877,799.823644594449,
806.823239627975,813.823123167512,820.928324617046,828.033350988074,831.576313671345,
835.118745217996,838.660801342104,842.202722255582,845.375651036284,848.548499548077,
851.721102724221,854.893733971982,858.069713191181,861.246083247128,864.42239005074,
867.599167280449,871.164374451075,874.730155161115,881.860434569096,889.002332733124,
896.144512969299,902.600150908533,909.057007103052,915.518407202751,921.979466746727,
928.458157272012,934.936859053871,941.413193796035,947.889697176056,957.103157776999,
966.31747558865,975.535038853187,984.752346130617,993.983722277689,1003.21515692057,
1012.44510323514,1021.67502918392,1030.94108681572,1040.20714747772,1049.47339519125,
1058.73964474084,1067.99884796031,1077.25820732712,1086.51761218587,1095.77706017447,
1107.73660275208,1119.69626377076,1131.65643793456,1143.61657934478,1155.58335018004,
1167.55013077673,1179.51667472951,1191.48321212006,1203.40613284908,1215.32905919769,
1227.25250144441,1239.17591887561,1251.09195255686,1263.00807951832,1274.92289851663,
1286.83736850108,1301.50151187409,1316.16494154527,1330.82828785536,1345.49177396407,
1360.14640453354,1374.80120013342,1389.45336885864,1404.10473555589,1415.46866941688,
1426.8322848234,1438.19593024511,1449.55961776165,1460.91077715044,1472.26207168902,
1483.61145226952,1494.96022184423,1503.93160504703,1512.90266238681,1521.87305141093,
1530.8435147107,1539.81428554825,1548.7850309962,1557.75612376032,1566.72723502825,
1575.77374641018,1584.82027791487,1593.86740284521,1602.91448650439,1611.95444362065,
1620.9945264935,1630.03290828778,1639.07079338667,1646.43628379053,1653.80156622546,
1661.16588263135,1668.53027571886,1675.89218094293,1683.25406776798,1690.61619777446,
1697.97832335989),.UNSPECIFIED.);
#523=CARTESIAN_POINT('',(-550.,650.,835.164654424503));
#524=VERTEX_POINT('',#523);
#525=EDGE_CURVE('E223',#524,#524,#522,.T.);
#526=ORIENTED_EDGE('',*,*,#525,.F.);
#527=EDGE_LOOP('',(#526));
#528=FACE_BOUND('',#527,.T.);
#529=CARTESIAN_POINT('',(0.,1000.,0.));
#530=DIRECTION('',(0.,1.,0.));
#531=DIRECTION('',(0.,0.,1.));
#532=AXIS2_PLACEMENT_3D('',#529,#530,#531);
#533=CIRCLE('',#532,1000.);
#534=CARTESIAN_POINT('',(0.,1000.,1000.));
#535=VERTEX_POINT('',#534);
#536=EDGE_CURVE('E210',#535,#535,#533,.T.);
#537=ORIENTED_EDGE('',*,*,#536,.F.);
#538=EDGE_LOOP('',(#537));
#539=FACE_BOUND('',#538,.T.);
#540=CARTESIAN_POINT('',(0.,0.,0.));
#541=DIRECTION('',(0.,1.,0.));
#542=DIRECTION('',(0.,0.,1.));
#543=AXIS2_PLACEMENT_3D('',#540,#541,#542);
#544=CIRCLE('',#543,1000.);
#545=CARTESIAN_POINT('',(0.,0.,1000.));
#546=VERTEX_POINT('',#545);
#547=EDGE_CURVE('E232',#546,#546,#544,.T.);
#548=ORIENTED_EDGE('',*,*,#547,.T.);
#549=EDGE_LOOP('',(#548));
#550=FACE_BOUND('',#549,.T.);
#551=CARTESIAN_POINT('',(550.,300.,-835.164654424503));
#552=CARTESIAN_POINT('',(549.999999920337,302.438202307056,-835.164654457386));
#553=CARTESIAN_POINT('',(550.044599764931,304.876402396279,-835.135288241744));
#554=CARTESIAN_POINT('',(550.222835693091,309.748126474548,-835.017869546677));
#555=CARTESIAN_POINT('',(550.356471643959,312.181650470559,-834.929817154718));
#556=CARTESIAN_POINT('',(550.712289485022,317.039346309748,-834.695165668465));
#557=CARTESIAN_POINT('',(550.934470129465,319.463518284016,-834.548567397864));
#558=CARTESIAN_POINT('',(551.466569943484,324.297960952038,-834.197053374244));
#559=CARTESIAN_POINT('',(551.776489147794,326.708231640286,-833.992137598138));
#560=CARTESIAN_POINT('',(552.482958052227,331.510449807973,-833.524301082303));
#561=CARTESIAN_POINT('',(552.879510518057,333.902396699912,-833.261378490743));
#562=CARTESIAN_POINT('',(553.757820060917,338.663506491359,-832.677941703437));
#563=CARTESIAN_POINT('',(554.239577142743,341.032669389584,-832.357427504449));
#564=CARTESIAN_POINT('',(555.286588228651,345.743966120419,-831.659305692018));
#565=CARTESIAN_POINT('',(555.851842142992,348.086099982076,-831.281698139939));
#566=CARTESIAN_POINT('',(557.063869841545,352.739263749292,-830.469973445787));
#567=CARTESIAN_POINT('',(557.710643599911,355.050293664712,-830.03585632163));
#568=CARTESIAN_POINT('',(559.081828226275,359.631833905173,-829.112893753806));
#569=CARTESIAN_POINT('',(559.806048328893,361.902428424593,-828.624182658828));
#570=CARTESIAN_POINT('',(561.330956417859,366.40513498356,-827.591931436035));
#571=CARTESIAN_POINT('',(562.131644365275,368.637247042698,-827.048391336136));
#572=CARTESIAN_POINT('',(563.806827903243,373.059518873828,-825.907311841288));
#573=CARTESIAN_POINT('',(564.681322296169,375.249679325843,-825.309773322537));
#574=CARTESIAN_POINT('',(566.50130203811,379.58488854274,-824.061582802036));
#575=CARTESIAN_POINT('',(567.44678743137,381.729937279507,-823.410930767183));
#576=CARTESIAN_POINT('',(569.405774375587,385.971995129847,-822.057468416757));
#577=CARTESIAN_POINT('',(570.419276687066,388.069003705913,-821.354657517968));
#578=CARTESIAN_POINT('',(572.511169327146,392.212258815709,-819.897911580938));
#579=CARTESIAN_POINT('',(573.589559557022,394.258505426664,-819.143976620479));
#580=CARTESIAN_POINT('',(575.80802247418,398.29783571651,-817.586055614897));
#581=CARTESIAN_POINT('',(576.948095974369,400.290918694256,-816.782068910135));
#582=CARTESIAN_POINT('',(579.286625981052,404.221754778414,-815.125179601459));
#583=CARTESIAN_POINT('',(580.48508349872,406.15950692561,-814.272276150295));
#584=CARTESIAN_POINT('',(582.988199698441,410.057462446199,-812.482137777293));
#585=CARTESIAN_POINT('',(584.295203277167,412.015225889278,-811.542868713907));
#586=CARTESIAN_POINT('',(586.965081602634,415.866760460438,-809.613923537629));
#587=CARTESIAN_POINT('',(588.327956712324,417.760531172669,-808.624247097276));
#588=CARTESIAN_POINT('',(591.105700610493,421.482483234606,-806.595938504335));
#589=CARTESIAN_POINT('',(592.520568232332,423.310666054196,-805.557307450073));
#590=CARTESIAN_POINT('',(595.398513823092,426.900246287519,-803.432516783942));
#591=CARTESIAN_POINT('',(596.861592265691,428.661643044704,-802.34635670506));
#592=CARTESIAN_POINT('',(599.832565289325,432.117125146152,-800.12769714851));
#593=CARTESIAN_POINT('',(601.340471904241,433.811192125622,-798.995185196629));
#594=CARTESIAN_POINT('',(604.39697994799,437.130780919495,-796.68560907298));
#595=CARTESIAN_POINT('',(605.945580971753,438.756303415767,-795.508545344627));
#596=CARTESIAN_POINT('',(609.080025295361,441.938539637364,-793.111225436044));
#597=CARTESIAN_POINT('',(610.665872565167,443.495245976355,-791.890964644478));
#598=CARTESIAN_POINT('',(613.871116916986,446.539458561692,-789.408868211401));
#599=CARTESIAN_POINT('',(615.490515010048,448.026962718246,-788.147031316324));
#600=CARTESIAN_POINT('',(619.400746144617,451.502822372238,-785.080299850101));
#601=CARTESIAN_POINT('',(621.705747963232,453.458723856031,-783.25656771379));
#602=CARTESIAN_POINT('',(626.365304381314,457.236955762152,-779.535372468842));
#603=CARTESIAN_POINT('',(628.719862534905,459.059276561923,-777.637904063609));
#604=CARTESIAN_POINT('',(633.470632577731,462.571939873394,-773.772793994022));
#605=CARTESIAN_POINT('',(635.866854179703,464.262251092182,-771.805135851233));
#606=CARTESIAN_POINT('',(640.692508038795,467.512192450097,-767.803968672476));
#607=CARTESIAN_POINT('',(643.121939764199,469.071824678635,-765.770460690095));
#608=CARTESIAN_POINT('',(648.010265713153,472.064869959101,-761.638334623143));
#609=CARTESIAN_POINT('',(650.46919716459,473.49809895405,-759.53962741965));
#610=CARTESIAN_POINT('',(655.406311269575,476.238490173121,-755.283516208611));
#611=CARTESIAN_POINT('',(657.884493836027,477.545652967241,-753.126112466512));
#612=CARTESIAN_POINT('',(662.853900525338,480.0368923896,-748.756071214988));
#613=CARTESIAN_POINT('',(665.345124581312,481.220969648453,-746.543433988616));
#614=CARTESIAN_POINT('',(670.335001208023,483.469281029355,-742.066186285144));
#615=CARTESIAN_POINT('',(672.833654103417,484.533509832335,-739.801573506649));
#616=CARTESIAN_POINT('',(678.711642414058,486.898983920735,-734.419144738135));
#617=CARTESIAN_POINT('',(682.091934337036,488.152117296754,-731.281132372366));
#618=CARTESIAN_POINT('',(688.845202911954,490.454244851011,-724.923305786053));
#619=CARTESIAN_POINT('',(692.218178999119,491.503223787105,-721.703485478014));
#620=CARTESIAN_POINT('',(698.94767166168,493.406022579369,-715.188151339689));
#621=CARTESIAN_POINT('',(702.304183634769,494.259790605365,-711.892617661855));
#622=CARTESIAN_POINT('',(708.991205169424,495.780581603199,-705.233109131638));
#623=CARTESIAN_POINT('',(712.321715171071,496.447607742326,-701.869135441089));
#624=CARTESIAN_POINT('',(718.952727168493,497.604162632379,-695.075197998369));
#625=CARTESIAN_POINT('',(722.253196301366,498.093515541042,-691.645172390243));
#626=CARTESIAN_POINT('',(728.814476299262,498.902236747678,-684.727818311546));
#627=CARTESIAN_POINT('',(732.075287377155,499.22160595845,-681.24049014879));
#628=CARTESIAN_POINT('',(738.551844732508,499.698479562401,-674.213617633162));
#629=CARTESIAN_POINT('',(741.767592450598,499.855989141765,-670.674074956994));
#630=CARTESIAN_POINT('',(748.149682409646,500.016913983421,-663.547238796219));
#631=CARTESIAN_POINT('',(751.316022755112,500.020323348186,-659.959943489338));
#632=CARTESIAN_POINT('',(758.948619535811,499.850243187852,-651.186483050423));
#633=CARTESIAN_POINT('',(763.387073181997,499.599891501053,-645.977463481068));
#634=CARTESIAN_POINT('',(772.146142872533,498.81872071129,-635.481760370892));
#635=CARTESIAN_POINT('',(776.466748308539,498.287876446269,-630.195069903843));
#636=CARTESIAN_POINT('',(784.984759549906,496.963577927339,-619.552580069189));
#637=CARTESIAN_POINT('',(789.182117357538,496.170022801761,-614.196754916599));
#638=CARTESIAN_POINT('',(797.446674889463,494.336638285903,-603.427602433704));
#639=CARTESIAN_POINT('',(801.513877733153,493.296814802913,-598.014276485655));
#640=CARTESIAN_POINT('',(809.521649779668,490.983176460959,-587.128976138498));
#641=CARTESIAN_POINT('',(813.461979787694,489.708946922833,-581.656914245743));
#642=CARTESIAN_POINT('',(821.205693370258,486.940250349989,-570.671857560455));
#643=CARTESIAN_POINT('',(825.009076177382,485.445782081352,-565.158862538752));
#644=CARTESIAN_POINT('',(832.476037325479,482.247621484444,-554.101204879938));
#645=CARTESIAN_POINT('',(836.139649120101,480.543979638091,-548.556550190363));
#646=CARTESIAN_POINT('',(843.32681673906,476.935792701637,-537.441787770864));
#647=CARTESIAN_POINT('',(846.850372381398,475.031247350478,-531.871680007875));
#648=CARTESIAN_POINT('',(852.092028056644,471.992706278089,-523.403029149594));
#649=CARTESIAN_POINT('',(853.861831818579,470.929723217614,-520.51072482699));
#650=CARTESIAN_POINT('',(857.363487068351,468.75228198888,-514.722537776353));
#651=CARTESIAN_POINT('',(859.095339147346,467.637824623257,-511.826655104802));
#652=CARTESIAN_POINT('',(862.521047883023,465.357936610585,-506.032380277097));
#653=CARTESIAN_POINT('',(864.214903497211,464.192504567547,-503.133988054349));
#654=CARTESIAN_POINT('',(867.564464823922,461.811060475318,-497.336011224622));
#655=CARTESIAN_POINT('',(869.220171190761,460.595049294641,-494.436426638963));
#656=CARTESIAN_POINT('',(872.494184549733,458.111979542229,-488.635850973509));
#657=CARTESIAN_POINT('',(874.112472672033,456.844896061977,-485.734859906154));
#658=CARTESIAN_POINT('',(877.31071108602,454.260203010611,-479.934250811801));
#659=CARTESIAN_POINT('',(878.890661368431,452.942593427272,-477.034632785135));
#660=CARTESIAN_POINT('',(882.012088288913,450.256607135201,-471.238274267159));
#661=CARTESIAN_POINT('',(883.553565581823,448.888231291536,-468.341533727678));
#662=CARTESIAN_POINT('',(886.597942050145,446.100180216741,-462.552466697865));
#663=CARTESIAN_POINT('',(888.100841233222,444.680504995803,-459.660140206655));
#664=CARTESIAN_POINT('',(891.067849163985,441.789113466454,-453.881742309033));
#665=CARTESIAN_POINT('',(892.531959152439,440.317398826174,-450.99567070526));
#666=CARTESIAN_POINT('',(895.421230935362,437.320783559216,-445.231638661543));
#667=CARTESIAN_POINT('',(896.84639268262,435.795882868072,-442.353678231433));
#668=CARTESIAN_POINT('',(899.657614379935,432.691311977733,-436.607841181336));
#669=CARTESIAN_POINT('',(901.043671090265,431.111637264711,-433.739965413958));
#670=CARTESIAN_POINT('',(903.776211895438,427.895773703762,-428.017071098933));
#671=CARTESIAN_POINT('',(905.122696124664,426.259585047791,-425.162052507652));
#672=CARTESIAN_POINT('',(907.774402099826,422.929912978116,-419.470477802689));
#673=CARTESIAN_POINT('',(909.079661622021,421.236485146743,-416.633906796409));
#674=CARTESIAN_POINT('',(911.649699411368,417.787942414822,-410.979888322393));
#675=CARTESIAN_POINT('',(912.914477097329,416.032826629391,-408.162441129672));
#676=CARTESIAN_POINT('',(915.40256622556,412.457696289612,-402.551311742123));
#677=CARTESIAN_POINT('',(916.625885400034,410.637693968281,-399.757625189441));
#678=CARTESIAN_POINT('',(919.030310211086,406.92820029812,-394.198501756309));
#679=CARTESIAN_POINT('',(920.211417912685,405.038712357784,-391.433063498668));
#680=CARTESIAN_POINT('',(922.373853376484,401.444759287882,-386.307047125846));
#681=CARTESIAN_POINT('',(923.360640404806,399.749711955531,-383.942170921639));
#682=CARTESIAN_POINT('',(925.30069231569,396.299452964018,-379.242784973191));
#683=CARTESIAN_POINT('',(926.253958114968,394.544242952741,-376.908274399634));
#684=CARTESIAN_POINT('',(928.126152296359,390.967851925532,-372.274217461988));
#685=CARTESIAN_POINT('',(929.045063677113,389.146639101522,-369.974688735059));
#686=CARTESIAN_POINT('',(930.846388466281,385.433264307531,-365.418938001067));
#687=CARTESIAN_POINT('',(931.728802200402,383.541102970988,-363.16271560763));
#688=CARTESIAN_POINT('',(933.450478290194,379.689081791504,-358.714179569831));
#689=CARTESIAN_POINT('',(934.289942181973,377.729627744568,-356.521593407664));
#690=CARTESIAN_POINT('',(935.927965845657,373.72564808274,-352.199068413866));
#691=CARTESIAN_POINT('',(936.726522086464,371.681115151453,-350.069134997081));
#692=CARTESIAN_POINT('',(938.278221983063,367.500212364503,-345.888629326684));
#693=CARTESIAN_POINT('',(939.031411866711,365.363939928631,-343.837977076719));
#694=CARTESIAN_POINT('',(940.488402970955,360.987594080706,-339.832459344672));
#695=CARTESIAN_POINT('',(941.19221816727,358.747550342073,-337.877566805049));
#696=CARTESIAN_POINT('',(942.126054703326,355.573488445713,-335.259732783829));
#697=CARTESIAN_POINT('',(942.379900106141,354.688525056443,-334.545487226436));
#698=CARTESIAN_POINT('',(942.879043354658,352.901188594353,-333.136110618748));
#699=CARTESIAN_POINT('',(943.124341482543,351.998816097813,-332.440978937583));
#700=CARTESIAN_POINT('',(943.846723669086,349.26462409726,-330.386844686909));
#701=CARTESIAN_POINT('',(944.310341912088,347.405573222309,-329.058972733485));
#702=CARTESIAN_POINT('',(945.197741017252,343.607905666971,-326.501249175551));
#703=CARTESIAN_POINT('',(945.621466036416,341.669182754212,-325.271535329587));
#704=CARTESIAN_POINT('',(946.422939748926,337.710814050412,-322.932110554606));
#705=CARTESIAN_POINT('',(946.800686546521,335.691164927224,-321.822404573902));
#706=CARTESIAN_POINT('',(947.508974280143,331.538979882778,-319.731107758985));
#707=CARTESIAN_POINT('',(947.838719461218,329.405202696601,-318.751695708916));
#708=CARTESIAN_POINT('',(948.436434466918,325.055814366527,-316.968793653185));
#709=CARTESIAN_POINT('',(948.704405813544,322.840205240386,-316.165299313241));
#710=CARTESIAN_POINT('',(949.053519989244,319.467185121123,-315.11513988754));
#711=CARTESIAN_POINT('',(949.160974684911,318.336137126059,-314.791266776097));
#712=CARTESIAN_POINT('',(949.357556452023,316.058344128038,-314.197911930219));
#713=CARTESIAN_POINT('',(949.446686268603,314.911601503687,-313.928422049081));
#714=CARTESIAN_POINT('',(949.605744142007,312.604898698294,-313.446957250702));
#715=CARTESIAN_POINT('',(949.675674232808,311.444939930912,-313.234976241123));
#716=CARTESIAN_POINT('',(949.795607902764,309.114601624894,-312.871123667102));
#717=CARTESIAN_POINT('',(949.84561224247,307.944222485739,-312.719249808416));
#718=CARTESIAN_POINT('',(949.920993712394,305.7187087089,-312.490189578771));
#719=CARTESIAN_POINT('',(949.948393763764,304.664270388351,-312.406870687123));
#720=CARTESIAN_POINT('',(949.986502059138,302.552314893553,-312.290969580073));
#721=CARTESIAN_POINT('',(949.997210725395,301.494797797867,-312.258386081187));
#722=CARTESIAN_POINT('',(950.001833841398,299.379470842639,-312.244320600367));
#723=CARTESIAN_POINT('',(949.995749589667,298.321661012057,-312.262834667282));
#724=CARTESIAN_POINT('',(949.9668481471,296.208383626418,-312.350747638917));
#725=CARTESIAN_POINT('',(949.94403080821,295.152916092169,-312.420146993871));
#726=CARTESIAN_POINT('',(949.88184538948,293.045866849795,-312.609164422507));
#727=CARTESIAN_POINT('',(949.842459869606,291.994290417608,-312.728835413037));
#728=CARTESIAN_POINT('',(949.747490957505,289.898495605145,-313.017134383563));
#729=CARTESIAN_POINT('',(949.69190557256,288.854278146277,-313.185768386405));
#730=CARTESIAN_POINT('',(949.565024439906,286.775579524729,-313.570255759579));
#731=CARTESIAN_POINT('',(949.493729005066,285.74109816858,-313.786108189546));
#732=CARTESIAN_POINT('',(949.336001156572,283.683644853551,-314.262978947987));
#733=CARTESIAN_POINT('',(949.249566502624,282.660674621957,-314.52400396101));
#734=CARTESIAN_POINT('',(949.050760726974,280.503678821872,-315.123412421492));
#735=CARTESIAN_POINT('',(948.936510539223,279.371368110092,-315.467352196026));
#736=CARTESIAN_POINT('',(948.690758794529,277.125129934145,-316.20562227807));
#737=CARTESIAN_POINT('',(948.559254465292,276.011205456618,-316.599960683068));
#738=CARTESIAN_POINT('',(948.140390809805,272.699157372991,-317.853070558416));
#739=CARTESIAN_POINT('',(947.82864230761,270.530348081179,-318.782053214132));
#740=CARTESIAN_POINT('',(947.147752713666,266.27434035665,-320.799421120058));
#741=CARTESIAN_POINT('',(946.778518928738,264.187280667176,-321.888063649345));
#742=CARTESIAN_POINT('',(945.990178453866,260.097791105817,-324.197579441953));
#743=CARTESIAN_POINT('',(945.571069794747,258.095364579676,-325.418457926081));
#744=CARTESIAN_POINT('',(944.731532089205,254.360839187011,-327.847253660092));
#745=CARTESIAN_POINT('',(944.315102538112,252.621257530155,-329.045135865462));
#746=CARTESIAN_POINT('',(943.450167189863,249.204939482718,-331.516962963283));
#747=CARTESIAN_POINT('',(943.001655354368,247.528215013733,-332.790922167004));
#748=CARTESIAN_POINT('',(942.075406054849,244.232897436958,-335.404013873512));
#749=CARTESIAN_POINT('',(941.597648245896,242.614346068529,-336.743191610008));
#750=CARTESIAN_POINT('',(940.615759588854,239.432651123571,-339.476216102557));
#751=CARTESIAN_POINT('',(940.111630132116,237.869504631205,-340.870059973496));
#752=CARTESIAN_POINT('',(939.077646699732,234.79042958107,-343.708395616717));
#753=CARTESIAN_POINT('',(938.547726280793,233.274641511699,-345.153015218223));
#754=CARTESIAN_POINT('',(937.465152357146,230.291069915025,-348.082643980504));
#755=CARTESIAN_POINT('',(936.912498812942,228.823286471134,-349.567653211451));
#756=CARTESIAN_POINT('',(935.786071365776,225.932864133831,-352.571980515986));
#757=CARTESIAN_POINT('',(935.21230525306,224.510208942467,-354.091285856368));
#758=CARTESIAN_POINT('',(934.044608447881,221.706398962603,-357.160139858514));
#759=CARTESIAN_POINT('',(933.45067723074,220.325245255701,-358.709689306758));
#760=CARTESIAN_POINT('',(931.988552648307,217.026156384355,-362.495537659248));
#761=CARTESIAN_POINT('',(931.110526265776,215.128037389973,-364.745322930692));
#762=CARTESIAN_POINT('',(929.317781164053,211.403131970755,-369.289085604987));
#763=CARTESIAN_POINT('',(928.403059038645,209.576352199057,-371.583067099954));
#764=CARTESIAN_POINT('',(926.538353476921,205.987768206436,-376.208585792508));
#765=CARTESIAN_POINT('',(925.5883577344,204.225987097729,-378.540135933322));
#766=CARTESIAN_POINT('',(923.65477106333,200.763149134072,-383.23401077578));
#767=CARTESIAN_POINT('',(922.671181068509,199.062090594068,-385.596334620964));
#768=CARTESIAN_POINT('',(920.669899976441,195.713880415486,-390.35060876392));
#769=CARTESIAN_POINT('',(919.652159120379,194.06681502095,-392.742598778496));
#770=CARTESIAN_POINT('',(917.584829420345,190.825738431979,-397.54864369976));
#771=CARTESIAN_POINT('',(916.535240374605,189.231727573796,-399.962698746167));
#772=CARTESIAN_POINT('',(914.405054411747,186.094016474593,-404.809093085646));
#773=CARTESIAN_POINT('',(913.324462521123,184.55030816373,-407.24142936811));
#774=CARTESIAN_POINT('',(911.132640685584,181.510408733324,-412.121907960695));
#775=CARTESIAN_POINT('',(910.021410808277,180.014217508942,-414.570050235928));
#776=CARTESIAN_POINT('',(907.764325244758,177.061460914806,-419.489310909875));
#777=CARTESIAN_POINT('',(906.618351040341,175.605073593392,-421.960481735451));
#778=CARTESIAN_POINT('',(904.296293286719,172.736260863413,-426.914156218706));
#779=CARTESIAN_POINT('',(903.120209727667,171.323835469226,-429.396659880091));
#780=CARTESIAN_POINT('',(900.738186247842,168.541439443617,-434.371183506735));
#781=CARTESIAN_POINT('',(899.532245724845,167.171469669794,-436.863203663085));
#782=CARTESIAN_POINT('',(897.090753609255,164.472803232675,-441.855066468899));
#783=CARTESIAN_POINT('',(895.855202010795,163.144106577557,-444.354909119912));
#784=CARTESIAN_POINT('',(893.355618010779,160.528005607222,-449.359050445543));
#785=CARTESIAN_POINT('',(892.09160798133,159.240570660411,-451.863344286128));
#786=CARTESIAN_POINT('',(889.534324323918,156.705148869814,-456.877013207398));
#787=CARTESIAN_POINT('',(888.241050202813,155.457162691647,-459.386388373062));
#788=CARTESIAN_POINT('',(885.625368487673,153.000070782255,-464.409004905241));
#789=CARTESIAN_POINT('',(884.302960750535,151.790965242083,-466.922246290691));
#790=CARTESIAN_POINT('',(881.629112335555,149.411222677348,-471.951500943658));
#791=CARTESIAN_POINT('',(880.277671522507,148.240585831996,-474.467514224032));
#792=CARTESIAN_POINT('',(877.147516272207,145.601702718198,-480.235270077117));
#793=CARTESIAN_POINT('',(875.359124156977,144.146215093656,-483.487610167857));
#794=CARTESIAN_POINT('',(871.734175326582,141.298700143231,-489.993259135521));
#795=CARTESIAN_POINT('',(869.897618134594,139.906673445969,-493.246568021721));
#796=CARTESIAN_POINT('',(866.17639319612,137.186124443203,-499.75243861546));
#797=CARTESIAN_POINT('',(864.291723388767,135.857604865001,-503.005000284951));
#798=CARTESIAN_POINT('',(860.47447498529,133.264538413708,-509.507498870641));
#799=CARTESIAN_POINT('',(858.541896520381,131.999991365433,-512.757435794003));
#800=CARTESIAN_POINT('',(854.627864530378,129.534865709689,-519.254855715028));
#801=CARTESIAN_POINT('',(852.646384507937,128.334322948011,-522.502336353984));
#802=CARTESIAN_POINT('',(848.635719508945,125.998908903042,-528.991459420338));
#803=CARTESIAN_POINT('',(846.606534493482,124.86403767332,-532.233101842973));
#804=CARTESIAN_POINT('',(842.500668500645,122.661189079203,-538.70893990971));
#805=CARTESIAN_POINT('',(840.423988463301,121.593210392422,-541.943135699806));
#806=CARTESIAN_POINT('',(836.22329922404,119.525561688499,-548.402622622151));
#807=CARTESIAN_POINT('',(834.099290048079,118.525891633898,-551.627913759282));
#808=CARTESIAN_POINT('',(829.812023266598,116.600045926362,-558.056339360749));
#809=CARTESIAN_POINT('',(827.648936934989,115.673615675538,-561.259511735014));
#810=CARTESIAN_POINT('',(823.276340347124,113.892097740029,-567.654005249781));
#811=CARTESIAN_POINT('',(821.066830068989,113.037010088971,-570.845326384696));
#812=CARTESIAN_POINT('',(816.601674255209,111.400234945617,-577.214719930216));
#813=CARTESIAN_POINT('',(814.346026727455,110.618550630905,-580.39279176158));
#814=CARTESIAN_POINT('',(809.78916492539,109.130934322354,-586.733970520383));
#815=CARTESIAN_POINT('',(807.487950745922,108.42500217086,-589.897077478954));
#816=CARTESIAN_POINT('',(802.841963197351,107.091825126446,-596.204759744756));
#817=CARTESIAN_POINT('',(800.497217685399,106.464531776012,-599.349345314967));
#818=CARTESIAN_POINT('',(795.763458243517,105.290851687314,-605.620303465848));
#819=CARTESIAN_POINT('',(793.374443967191,104.744465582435,-608.746675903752));
#820=CARTESIAN_POINT('',(788.553252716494,103.735608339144,-614.97909503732));
#821=CARTESIAN_POINT('',(786.121080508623,103.273127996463,-618.085143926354));
#822=CARTESIAN_POINT('',(781.214398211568,102.435186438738,-624.27530986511));
#823=CARTESIAN_POINT('',(778.739889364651,102.05972267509,-627.359427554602));
#824=CARTESIAN_POINT('',(773.173708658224,101.322935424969,-634.213011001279));
#825=CARTESIAN_POINT('',(770.071401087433,100.984873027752,-637.976379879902));
#826=CARTESIAN_POINT('',(763.807056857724,100.452396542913,-645.463091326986));
#827=CARTESIAN_POINT('',(760.645023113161,100.257975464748,-649.186435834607));
#828=CARTESIAN_POINT('',(754.264241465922,100.019978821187,-656.58916513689));
#829=CARTESIAN_POINT('',(751.045493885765,99.9764023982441,-660.26855018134));
#830=CARTESIAN_POINT('',(744.555061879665,100.047792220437,-667.578947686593));
#831=CARTESIAN_POINT('',(741.28337694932,100.162759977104,-671.209959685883));
#832=CARTESIAN_POINT('',(734.693665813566,100.559269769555,-678.416569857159));
#833=CARTESIAN_POINT('',(731.375668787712,100.840711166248,-681.992200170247));
#834=CARTESIAN_POINT('',(724.696794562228,101.578641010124,-689.085106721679));
#835=CARTESIAN_POINT('',(721.33591688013,102.035131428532,-692.602382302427));
#836=CARTESIAN_POINT('',(714.578382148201,103.131963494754,-699.572220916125));
#837=CARTESIAN_POINT('',(711.181731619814,103.772272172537,-703.024795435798));
#838=CARTESIAN_POINT('',(704.359731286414,105.245943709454,-709.859618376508));
#839=CARTESIAN_POINT('',(700.934383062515,106.079295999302,-713.241870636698));
#840=CARTESIAN_POINT('',(694.834755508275,107.73866699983,-719.179040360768));
#841=CARTESIAN_POINT('',(692.164403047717,108.524375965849,-721.749312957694));
#842=CARTESIAN_POINT('',(686.81649822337,110.221931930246,-726.840233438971));
#843=CARTESIAN_POINT('',(684.138946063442,111.133775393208,-729.360882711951));
#844=CARTESIAN_POINT('',(678.781891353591,113.087961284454,-734.349058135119));
#845=CARTESIAN_POINT('',(676.102388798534,114.130304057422,-736.816584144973));
#846=CARTESIAN_POINT('',(670.747320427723,116.349752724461,-741.694782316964));
#847=CARTESIAN_POINT('',(668.071754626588,117.526859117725,-744.105454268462));
#848=CARTESIAN_POINT('',(662.734067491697,120.018550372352,-748.863354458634));
#849=CARTESIAN_POINT('',(660.071934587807,121.332982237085,-751.210649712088));
#850=CARTESIAN_POINT('',(654.765316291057,124.104249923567,-755.84044554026));
#851=CARTESIAN_POINT('',(652.12083110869,125.561087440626,-758.122945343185));
#852=CARTESIAN_POINT('',(646.857916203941,128.620382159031,-762.618391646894));
#853=CARTESIAN_POINT('',(644.239482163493,130.222814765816,-764.83134981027));
#854=CARTESIAN_POINT('',(639.036932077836,133.57651989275,-769.183527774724));
#855=CARTESIAN_POINT('',(636.452814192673,135.327784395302,-771.32275153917));
#856=CARTESIAN_POINT('',(631.865089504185,138.598848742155,-775.082814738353));
#857=CARTESIAN_POINT('',(629.853275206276,140.090284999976,-776.718370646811));
#858=CARTESIAN_POINT('',(625.86188780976,143.168624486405,-779.938119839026));
#859=CARTESIAN_POINT('',(623.882313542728,144.755524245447,-781.522314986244));
#860=CARTESIAN_POINT('',(619.96072072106,148.02532123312,-784.636842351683));
#861=CARTESIAN_POINT('',(618.018699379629,149.708211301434,-786.167178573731));
#862=CARTESIAN_POINT('',(614.177500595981,153.170391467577,-789.17168172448));
#863=CARTESIAN_POINT('',(612.27832350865,154.949682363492,-790.645848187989));
#864=CARTESIAN_POINT('',(608.528466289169,158.604596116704,-793.535575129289));
#865=CARTESIAN_POINT('',(606.677787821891,160.480222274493,-794.951133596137));
#866=CARTESIAN_POINT('',(603.030905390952,164.327195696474,-797.721110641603));
#867=CARTESIAN_POINT('',(601.23470127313,166.298542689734,-799.075529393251));
#868=CARTESIAN_POINT('',(597.702770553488,170.33601893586,-801.720815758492));
#869=CARTESIAN_POINT('',(595.967046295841,172.402151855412,-803.011680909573));
#870=CARTESIAN_POINT('',(592.56235444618,176.627599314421,-805.527365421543));
#871=CARTESIAN_POINT('',(590.893386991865,178.786914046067,-806.752184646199));
#872=CARTESIAN_POINT('',(587.614777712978,183.215186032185,-809.143389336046));
#873=CARTESIAN_POINT('',(586.005752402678,185.484912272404,-810.309197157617));
#874=CARTESIAN_POINT('',(582.868461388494,190.114299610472,-812.568824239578));
#875=CARTESIAN_POINT('',(581.340195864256,192.473960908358,-813.662643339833));
#876=CARTESIAN_POINT('',(578.370773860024,197.280050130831,-815.776053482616));
#877=CARTESIAN_POINT('',(576.929623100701,199.726483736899,-816.795639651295));
#878=CARTESIAN_POINT('',(574.140888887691,204.702014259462,-818.758296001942));
#879=CARTESIAN_POINT('',(572.793305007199,207.231110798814,-819.701366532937));
#880=CARTESIAN_POINT('',(570.198888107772,212.365380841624,-821.508201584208));
#881=CARTESIAN_POINT('',(568.951976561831,214.970492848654,-822.372027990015));
#882=CARTESIAN_POINT('',(566.563611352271,220.253558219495,-824.019283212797));
#883=CARTESIAN_POINT('',(565.422159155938,222.931512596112,-824.802710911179));
#884=CARTESIAN_POINT('',(563.250522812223,228.353918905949,-826.28722515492));
#885=CARTESIAN_POINT('',(562.220317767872,231.098358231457,-826.98832716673));
#886=CARTESIAN_POINT('',(560.276146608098,236.647792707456,-828.30671827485));
#887=CARTESIAN_POINT('',(559.36217410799,239.452784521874,-828.9240119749));
#888=CARTESIAN_POINT('',(557.813112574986,244.59231961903,-829.967007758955));
#889=CARTESIAN_POINT('',(557.157713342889,246.917870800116,-830.40702584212));
#890=CARTESIAN_POINT('',(555.929487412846,251.60067384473,-831.229782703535));
#891=CARTESIAN_POINT('',(555.356658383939,253.957924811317,-831.612523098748));
#892=CARTESIAN_POINT('',(554.295668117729,258.699681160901,-832.320081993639));
#893=CARTESIAN_POINT('',(553.807495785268,261.084182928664,-832.644908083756));
#894=CARTESIAN_POINT('',(552.917470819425,265.876457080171,-833.236194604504));
#895=CARTESIAN_POINT('',(552.515619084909,268.284229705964,-833.502654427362));
#896=CARTESIAN_POINT('',(551.799822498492,273.11773081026,-833.976702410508));
#897=CARTESIAN_POINT('',(551.485847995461,275.543452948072,-834.184310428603));
#898=CARTESIAN_POINT('',(550.946774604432,280.40906781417,-834.540445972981));
#899=CARTESIAN_POINT('',(550.721675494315,282.848960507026,-834.688973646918));
#900=CARTESIAN_POINT('',(550.361174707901,287.738328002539,-834.926717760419));
#901=CARTESIAN_POINT('',(550.225775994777,290.187803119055,-835.015932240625));
#902=CARTESIAN_POINT('',(550.045188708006,295.091519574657,-835.134900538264));
#903=CARTESIAN_POINT('',(550.000000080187,297.54576091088,-835.164654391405));
#904=CARTESIAN_POINT('',(550.,300.,-835.164654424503));
#905=B_SPLINE_CURVE_WITH_KNOTS('',3,(#551,#552,#553,#554,#555,#556,#557,#558,#559,#560,#561,
#562,#563,#564,#565,#566,#567,#568,#569,#570,#571,#572,#573,#574,#575,#576,#577,#578,#579,#580,
#581,#582,#583,#584,#585,#586,#587,#588,#589,#590,#591,#592,#593,#594,#595,#596,#597,#598,#599,
#600,#601,#602,#603,#604,#605,#606,#607,#608,#609,#610,#611,#612,#613,#614,#615,#616,#617,#618,
#619,#620,#621,#622,#623,#624,#625,#626,#627,#628,#629,#630,#631,#632,#633,#634,#635,#636,#637,
#638,#639,#640,#641,#642,#643,#644,#645,#646,#647,#648,#649,#650,#651,#652,#653,#654,#655,#656,
#657,#658,#659,#660,#661,#662,#663,#664,#665,#666,#667,#668,#669,#670,#671,#672,#673,#674,#675,
#676,#677,#678,#679,#680,#681,#682,#683,#684,#685,#686,#687,#688,#689,#690,#691,#692,#693,#694,
#695,#696,#697,#698,#699,#700,#701,#702,#703,#704,#705,#706,#707,#708,#709,#710,#711,#712,#713,
#714,#715,#716,#717,#718,#719,#720,#721,#722,#723,#724,#725,#726,#727,#728,#729,#730,#731,#732,
#733,#734,#735,#736,#737,#738,#739,#740,#741,#742,#743,#744,#745,#746,#747,#748,#749,#750,#751,
#752,#753,#754,#755,#756,#757,#758,#759,#760,#761,#762,#763,#764,#765,#766,#767,#768,#769,#770,
#771,#772,#773,#774,#775,#776,#777,#778,#779,#780,#781,#782,#783,#784,#785,#786,#787,#788,#789,
#790,#791,#792,#793,#794,#795,#796,#797,#798,#799,#800,#801,#802,#803,#804,#805,#806,#807,#808,
#809,#810,#811,#812,#813,#814,#815,#816,#817,#818,#819,#820,#821,#822,#823,#824,#825,#826,#827,
#828,#829,#830,#831,#832,#833,#834,#835,#836,#837,#838,#839,#840,#841,#842,#843,#844,#845,#846,
#847,#848,#849,#850,#851,#852,#853,#854,#855,#856,#857,#858,#859,#860,#861,#862,#863,#864,#865,
#866,#867,#868,#869,#870,#871,#872,#873,#874,#875,#876,#877,#878,#879,#880,#881,#882,#883,#884,
#885,#886,#887,#888,#889,#890,#891,#892,#893,#894,#895,#896,#897,#898,#899,#900,#901,#902,#903,
#904),.UNSPECIFIED.,.T.,.F.,(4,2,2,2,2,2,2,2,2,2,2,2,2,2,2,2,2,2,2,2,2,2,2,2,2,2,2,2,2,2,2,2,2,
2,2,2,2,2,2,2,2,2,2,2,2,2,2,2,2,2,2,2,2,2,2,2,2,2,2,2,2,2,2,2,2,2,2,2,2,2,2,2,2,2,2,2,2,2,2,2,2,
2,2,2,2,2,2,2,2,2,2,2,2,2,2,2,2,2,2,2,2,2,2,2,2,2,2,2,2,2,2,2,2,2,2,2,2,2,2,2,2,2,2,2,2,2,2,2,2,
2,2,2,2,2,2,2,2,2,2,2,2,2,2,2,2,2,2,2,2,2,2,2,2,2,2,2,2,2,2,2,2,2,2,2,2,2,2,2,2,2,2,2,2,2,2,2,
4),(0.,7.31401910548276,14.6280273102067,21.9419326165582,29.2558408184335,36.5699825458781,
43.8841246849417,51.1982589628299,58.512390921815,65.8089045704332,73.105414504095,
80.4018060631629,87.698202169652,94.994679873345,102.29114647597,109.587709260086,
116.884398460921,124.485705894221,132.087062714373,139.688249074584,147.289510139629,
154.892830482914,162.496075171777,170.100133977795,177.704422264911,188.292011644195,
198.880362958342,209.471216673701,220.061901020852,230.66776037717,241.273571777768,
251.879328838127,262.485556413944,276.818530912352,291.1525750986,305.490420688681,
319.828023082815,334.179776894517,348.531453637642,362.882670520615,377.234436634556,
397.770649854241,418.308705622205,438.854656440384,459.400114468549,479.982274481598,
500.564549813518,521.141867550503,541.719212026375,552.379319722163,563.03926125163,
573.699494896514,584.359545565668,595.024859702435,605.690176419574,616.355311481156,
627.020444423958,637.685235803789,648.350040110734,659.015725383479,669.681374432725,
680.336948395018,690.992675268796,701.646403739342,712.299610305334,721.515946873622,
730.732031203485,739.952617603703,749.17312170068,758.345405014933,767.518478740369,
776.682041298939,785.842999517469,789.338404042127,792.833693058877,799.823644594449,
806.823239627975,813.823123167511,820.928324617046,828.033350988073,831.576313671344,
835.118745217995,838.660801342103,842.202722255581,845.375651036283,848.548499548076,
851.72110272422,854.893733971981,858.06971319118,861.246083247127,864.422390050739,
867.599167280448,871.164374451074,874.730155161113,881.860434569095,889.002332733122,
896.144512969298,902.600150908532,909.057007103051,915.51840720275,921.979466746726,
928.458157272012,934.936859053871,941.413193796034,947.889697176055,957.103157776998,
966.317475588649,975.535038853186,984.752346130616,993.983722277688,1003.21515692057,
1012.44510323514,1021.67502918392,1030.94108681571,1040.20714747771,1049.47339519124,
1058.73964474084,1067.99884796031,1077.25820732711,1086.51761218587,1095.77706017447,
1107.73660275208,1119.69626377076,1131.65643793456,1143.61657934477,1155.58335018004,
1167.55013077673,1179.51667472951,1191.48321212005,1203.40613284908,1215.32905919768,
1227.25250144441,1239.17591887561,1251.09195255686,1263.00807951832,1274.92289851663,
1286.83736850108,1301.50151187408,1316.16494154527,1330.82828785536,1345.49177396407,
1360.14640453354,1374.80120013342,1389.45336885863,1404.10473555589,1415.46866941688,
1426.8322848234,1438.1959302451,1449.55961776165,1460.91077715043,1472.26207168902,
1483.61145226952,1494.96022184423,1503.93160504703,1512.90266238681,1521.87305141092,
1530.8435147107,1539.81428554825,1548.7850309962,1557.75612376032,1566.72723502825,
1575.77374641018,1584.82027791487,1593.86740284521,1602.91448650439,1611.95444362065,
1620.9945264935,1630.03290828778,1639.07079338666,1646.43628379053,1653.80156622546,
1661.16588263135,1668.53027571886,1675.89218094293,1683.25406776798,1690.61619777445,
1697.97832335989),.UNSPECIFIED.);
#906=CARTESIAN_POINT('',(550.,300.,-835.164654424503));
#907=VERTEX_POINT('',#906);
#908=EDGE_CURVE('E196',#907,#907,#905,.T.);
#909=ORIENTED_EDGE('',*,*,#908,.F.);
#910=EDGE_LOOP('',(#909));
#911=FACE_BOUND('',#910,.T.);
#912=ADVANCED_FACE('F192',(#528,#539,#550,#911),#167,.T.);
#913=CARTESIAN_POINT('',(0.,1000.,0.));
#914=DIRECTION('',(0.,1.,0.));
#915=DIRECTION('',(0.,0.,1.));
#916=AXIS2_PLACEMENT_3D('',#913,#914,#915);
#917=PLANE('',#916);
#918=ORIENTED_EDGE('',*,*,#536,.T.);
#919=EDGE_LOOP('',(#918));
#920=FACE_BOUND('',#919,.T.);
#921=ADVANCED_FACE('F253',(#920),#917,.T.);
#922=CARTESIAN_POINT('',(0.,0.,0.));
#923=DIRECTION('',(0.,1.,0.));
#924=DIRECTION('',(0.,0.,1.));
#925=AXIS2_PLACEMENT_3D('',#922,#923,#924);
#926=PLANE('',#925);
#927=CARTESIAN_POINT('',(0.,0.,0.));
#928=DIRECTION('',(0.,-1.,0.));
#929=DIRECTION('',(0.,0.,-1.));
#930=AXIS2_PLACEMENT_3D('',#927,#928,#929);
#931=CIRCLE('',#930,200.);
#932=CARTESIAN_POINT('',(0.,0.,-200.));
#933=VERTEX_POINT('',#932);
#934=EDGE_CURVE('E152',#933,#933,#931,.T.);
#935=ORIENTED_EDGE('',*,*,#934,.F.);
#936=EDGE_LOOP('',(#935));
#937=FACE_BOUND('',#936,.T.);
#938=ORIENTED_EDGE('',*,*,#547,.F.);
#939=EDGE_LOOP('',(#938));
#940=FACE_BOUND('',#939,.T.);
#941=ADVANCED_FACE('F243',(#937,#940),#926,.F.);
#942=CARTESIAN_POINT('',(-750.,650.,1600.));
#943=DIRECTION('',(0.,0.,1.));
#944=DIRECTION('',(1.,0.,0.));
#945=AXIS2_PLACEMENT_3D('',#942,#943,#944);
#946=PLANE('',#945);
#947=CARTESIAN_POINT('',(-750.,650.,1600.));
#948=DIRECTION('',(0.,0.,1.));
#949=DIRECTION('',(1.,0.,0.));
#950=AXIS2_PLACEMENT_3D('',#947,#948,#949);
#951=CIRCLE('',#950,190.);
#952=CARTESIAN_POINT('',(-560.,650.,1600.));
#953=VERTEX_POINT('',#952);
#954=EDGE_CURVE('E333',#953,#953,#951,.T.);
#955=ORIENTED_EDGE('',*,*,#954,.F.);
#956=EDGE_LOOP('',(#955));
#957=FACE_BOUND('',#956,.T.);
#958=CARTESIAN_POINT('',(-750.,650.,1600.));
#959=DIRECTION('',(0.,0.,1.));
#960=DIRECTION('',(1.,0.,0.));
#961=AXIS2_PLACEMENT_3D('',#958,#959,#960);
#962=CIRCLE('',#961,200.);
#963=CARTESIAN_POINT('',(-550.,650.,1600.));
#964=VERTEX_POINT('',#963);
#965=EDGE_CURVE('E219',#964,#964,#962,.T.);
#966=ORIENTED_EDGE('',*,*,#965,.T.);
#967=EDGE_LOOP('',(#966));
#968=FACE_BOUND('',#967,.T.);
#969=ADVANCED_FACE('F241',(#957,#968),#946,.T.);
#970=CARTESIAN_POINT('',(-750.,650.,-1000.001));
#971=DIRECTION('',(0.,0.,1.));
#972=DIRECTION('',(1.,0.,0.));
#973=AXIS2_PLACEMENT_3D('',#970,#971,#972);
#974=CYLINDRICAL_SURFACE('',#973,200.);
#975=ORIENTED_EDGE('',*,*,#965,.F.);
#976=EDGE_LOOP('',(#975));
#977=FACE_BOUND('',#976,.T.);
#978=ORIENTED_EDGE('',*,*,#525,.T.);
#979=EDGE_LOOP('',(#978));
#980=FACE_BOUND('',#979,.T.);
#981=ADVANCED_FACE('F233',(#977,#980),#974,.T.);
#982=CARTESIAN_POINT('',(750.,300.,-1600.));
#983=DIRECTION('',(0.,0.,1.));
#984=DIRECTION('',(1.,0.,0.));
#985=AXIS2_PLACEMENT_3D('',#982,#983,#984);
#986=PLANE('',#985);
#987=CARTESIAN_POINT('',(750.,300.,-1600.));
#988=DIRECTION('',(0.,0.,1.));
#989=DIRECTION('',(1.,0.,0.));
#990=AXIS2_PLACEMENT_3D('',#987,#988,#989);
#991=CIRCLE('',#990,190.);
#992=CARTESIAN_POINT('',(940.,300.,-1600.));
#993=VERTEX_POINT('',#992);
#994=EDGE_CURVE('E332',#993,#993,#991,.T.);
#995=ORIENTED_EDGE('',*,*,#994,.T.);
#996=EDGE_LOOP('',(#995));
#997=FACE_BOUND('',#996,.T.);
#998=CARTESIAN_POINT('',(750.,300.,-1600.));
#999=DIRECTION('',(0.,0.,1.));
#1000=DIRECTION('',(1.,0.,0.));
#1001=AXIS2_PLACEMENT_3D('',#998,#999,#1000);
#1002=CIRCLE('',#1001,200.);
#1003=CARTESIAN_POINT('',(950.,300.,-1600.));
#1004=VERTEX_POINT('',#1003);
#1005=EDGE_CURVE('E215',#1004,#1004,#1002,.T.);
#1006=ORIENTED_EDGE('',*,*,#1005,.F.);
#1007=EDGE_LOOP('',(#1006));
#1008=FACE_BOUND('',#1007,.T.);
#1009=ADVANCED_FACE('F250',(#997,#1008),#986,.F.);
#1010=CARTESIAN_POINT('',(750.,300.,1600.001));
#1011=DIRECTION('',(0.,0.,-1.));
#1012=DIRECTION('',(-1.,0.,0.));
#1013=AXIS2_PLACEMENT_3D('',#1010,#1011,#1012);
#1014=CYLINDRICAL_SURFACE('',#1013,200.);
#1015=ORIENTED_EDGE('',*,*,#1005,.T.);
#1016=EDGE_LOOP('',(#1015));
#1017=FACE_BOUND('',#1016,.T.);
#1018=ORIENTED_EDGE('',*,*,#908,.T.);
#1019=EDGE_LOOP('',(#1018));
#1020=FACE_BOUND('',#1019,.T.);
#1021=ADVANCED_FACE('F238',(#1017,#1020),#1014,.T.);
#1022=CARTESIAN_POINT('',(0.,-1000.,0.));
#1023=DIRECTION('',(0.,1.,0.));
#1024=DIRECTION('',(0.,0.,1.));
#1025=AXIS2_PLACEMENT_3D('',#1022,#1023,#1024);
#1026=CYLINDRICAL_SURFACE('',#1025,200.);
#1027=CARTESIAN_POINT('',(0.,-1000.,0.));
#1028=DIRECTION('',(0.,-1.,0.));
#1029=DIRECTION('',(0.,0.,-1.));
#1030=AXIS2_PLACEMENT_3D('',#1027,#1028,#1029);
#1031=CIRCLE('',#1030,200.);
#1032=CARTESIAN_POINT('',(0.,-1000.,-200.));
#1033=VERTEX_POINT('',#1032);
#1034=EDGE_CURVE('E213',#1033,#1033,#1031,.T.);
#1035=ORIENTED_EDGE('',*,*,#1034,.F.);
#1036=EDGE_LOOP('',(#1035));
#1037=FACE_BOUND('',#1036,.T.);
#1038=ORIENTED_EDGE('',*,*,#934,.T.);
#1039=EDGE_LOOP('',(#1038));
#1040=FACE_BOUND('',#1039,.T.);
#1041=ADVANCED_FACE('F274',(#1037,#1040),#1026,.T.);
#1042=CARTESIAN_POINT('',(0.,-1000.,0.));
#1043=DIRECTION('',(0.,-1.,0.));
#1044=DIRECTION('',(0.,0.,-1.));
#1045=AXIS2_PLACEMENT_3D('',#1042,#1043,#1044);
#1046=PLANE('',#1045);
#1047=CARTESIAN_POINT('',(0.,-1000.,0.));
#1048=DIRECTION('',(0.,-1.,0.));
#1049=DIRECTION('',(0.,0.,-1.));
#1050=AXIS2_PLACEMENT_3D('',#1047,#1048,#1049);
#1051=CIRCLE('',#1050,190.);
#1052=CARTESIAN_POINT('',(0.,-1000.,-190.));
#1053=VERTEX_POINT('',#1052);
#1054=EDGE_CURVE('E328',#1053,#1053,#1051,.T.);
#1055=ORIENTED_EDGE('',*,*,#1054,.F.);
#1056=EDGE_LOOP('',(#1055));
#1057=FACE_BOUND('',#1056,.T.);
#1058=ORIENTED_EDGE('',*,*,#1034,.T.);
#1059=EDGE_LOOP('',(#1058));
#1060=FACE_BOUND('',#1059,.T.);
#1061=ADVANCED_FACE('F278',(#1057,#1060),#1046,.T.);
#1062=CARTESIAN_POINT('',(0.,1000.,0.));
#1063=DIRECTION('',(0.,-1.,0.));
#1064=DIRECTION('',(0.,0.,-1.));
#1065=AXIS2_PLACEMENT_3D('',#1062,#1063,#1064);
#1066=CYLINDRICAL_SURFACE('',#1065,990.);
#1067=CARTESIAN_POINT('',(-939.885615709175,656.59188491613,310.990400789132));
#1068=CARTESIAN_POINT('',(-939.949372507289,654.755111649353,310.797715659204));
#1069=CARTESIAN_POINT('',(-939.986716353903,652.908850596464,310.684686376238));
#1070=CARTESIAN_POINT('',(-940.007358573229,649.213181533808,310.622225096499));
#1071=CARTESIAN_POINT('',(-939.990653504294,647.363773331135,310.672803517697));
#1072=CARTESIAN_POINT('',(-939.903709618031,643.676713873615,310.935741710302));
#1073=CARTESIAN_POINT('',(-939.833437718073,641.839070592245,311.148201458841));
#1074=CARTESIAN_POINT('',(-939.641474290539,638.191173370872,311.727432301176));
#1075=CARTESIAN_POINT('',(-939.519781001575,636.380920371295,312.09420868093));
#1076=CARTESIAN_POINT('',(-939.229597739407,632.814724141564,312.966405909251));
#1077=CARTESIAN_POINT('',(-939.061515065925,631.058449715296,313.470619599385));
#1078=CARTESIAN_POINT('',(-938.682088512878,627.592185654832,314.604980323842));
#1079=CARTESIAN_POINT('',(-938.470744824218,625.882195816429,315.235126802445));
#1080=CARTESIAN_POINT('',(-938.008859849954,622.512501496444,316.606857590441));
#1081=CARTESIAN_POINT('',(-937.758303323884,620.852816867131,317.348485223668));
#1082=CARTESIAN_POINT('',(-937.222030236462,617.586242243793,318.928772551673));
#1083=CARTESIAN_POINT('',(-936.936310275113,615.979357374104,319.76744162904));
#1084=CARTESIAN_POINT('',(-936.349217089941,612.901572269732,321.482381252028));
#1085=CARTESIAN_POINT('',(-936.049453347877,611.427961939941,322.354365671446));
#1086=CARTESIAN_POINT('',(-935.424338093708,608.526911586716,324.163884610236));
#1087=CARTESIAN_POINT('',(-935.098981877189,607.099480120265,325.101431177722));
#1088=CARTESIAN_POINT('',(-934.424876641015,604.288342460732,327.033940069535));
#1089=CARTESIAN_POINT('',(-934.076111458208,602.904667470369,328.028941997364));
#1090=CARTESIAN_POINT('',(-933.357447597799,600.180010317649,330.068241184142));
#1091=CARTESIAN_POINT('',(-932.987549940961,598.839026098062,331.112536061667));
#1092=CARTESIAN_POINT('',(-932.226992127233,596.192701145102,333.247842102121));
#1093=CARTESIAN_POINT('',(-931.836263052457,594.887503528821,334.339005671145));
#1094=CARTESIAN_POINT('',(-931.036728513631,592.315368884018,336.559062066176));
#1095=CARTESIAN_POINT('',(-930.627923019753,591.048431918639,337.687954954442));
#1096=CARTESIAN_POINT('',(-929.793627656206,588.55096256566,339.978374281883));
#1097=CARTESIAN_POINT('',(-929.368143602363,587.32041774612,341.139889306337));
#1098=CARTESIAN_POINT('',(-928.501402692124,584.893089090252,343.491945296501));
#1099=CARTESIAN_POINT('',(-928.060145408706,583.696306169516,344.682487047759));
#1100=CARTESIAN_POINT('',(-926.987850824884,580.874142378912,347.558209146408));
#1101=CARTESIAN_POINT('',(-926.349881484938,579.26353085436,349.255310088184));
#1102=CARTESIAN_POINT('',(-925.047142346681,576.09853621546,352.691311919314));
#1103=CARTESIAN_POINT('',(-924.382369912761,574.544158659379,354.430216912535));
#1104=CARTESIAN_POINT('',(-923.027383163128,571.486807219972,357.944125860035));
#1105=CARTESIAN_POINT('',(-922.33715940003,569.983852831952,359.719143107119));
#1106=CARTESIAN_POINT('',(-920.932791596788,567.026145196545,363.299451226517));
#1107=CARTESIAN_POINT('',(-920.218648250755,565.571390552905,365.104741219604));
#1108=CARTESIAN_POINT('',(-918.766266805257,562.704332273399,368.744345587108));
#1109=CARTESIAN_POINT('',(-918.027991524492,561.292101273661,370.578702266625));
#1110=CARTESIAN_POINT('',(-916.52927956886,558.509584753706,374.270020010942));
#1111=CARTESIAN_POINT('',(-915.768842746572,557.139299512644,376.126981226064));
#1112=CARTESIAN_POINT('',(-914.226628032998,554.438331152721,379.86017271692));
#1113=CARTESIAN_POINT('',(-913.444853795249,553.107641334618,381.736399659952));
#1114=CARTESIAN_POINT('',(-911.860405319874,550.483376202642,385.505876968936));
#1115=CARTESIAN_POINT('',(-911.057731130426,549.189800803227,387.399127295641));
#1116=CARTESIAN_POINT('',(-909.428316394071,546.632106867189,391.208958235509));
#1117=CARTESIAN_POINT('',(-908.601484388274,545.368145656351,393.125605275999));
#1118=CARTESIAN_POINT('',(-906.927592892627,542.873970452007,396.971964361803));
#1119=CARTESIAN_POINT('',(-906.08053339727,541.643756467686,398.901676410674));
#1120=CARTESIAN_POINT('',(-904.366503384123,539.215564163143,402.77252612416));
#1121=CARTESIAN_POINT('',(-903.499532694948,538.017586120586,404.713663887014));
#1122=CARTESIAN_POINT('',(-901.745953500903,535.652581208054,408.605913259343));
#1123=CARTESIAN_POINT('',(-900.859344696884,534.485554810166,410.557025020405));
#1124=CARTESIAN_POINT('',(-898.171871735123,531.031057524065,416.420174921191));
#1125=CARTESIAN_POINT('',(-896.341933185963,528.788150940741,420.345254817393));
#1126=CARTESIAN_POINT('',(-892.60597111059,524.414141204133,428.221416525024));
#1127=CARTESIAN_POINT('',(-890.699945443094,522.283041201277,432.172499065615));
#1128=CARTESIAN_POINT('',(-887.162505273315,518.501370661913,439.38113418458));
#1129=CARTESIAN_POINT('',(-885.543379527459,516.833327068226,442.635571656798));
#1130=CARTESIAN_POINT('',(-882.254985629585,513.566903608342,449.154168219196));
#1131=CARTESIAN_POINT('',(-880.585716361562,511.968525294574,452.41832752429));
#1132=CARTESIAN_POINT('',(-877.197232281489,508.839871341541,458.95377291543));
#1133=CARTESIAN_POINT('',(-875.47801303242,507.309601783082,462.225059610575));
#1134=CARTESIAN_POINT('',(-871.990019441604,504.316382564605,468.77197340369));
#1135=CARTESIAN_POINT('',(-870.221245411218,502.853432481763,472.047600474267));
#1136=CARTESIAN_POINT('',(-866.632983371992,499.993283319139,478.603433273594));
#1137=CARTESIAN_POINT('',(-864.813458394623,498.596134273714,481.883640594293));
#1138=CARTESIAN_POINT('',(-861.125125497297,495.868669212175,488.444141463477));
#1139=CARTESIAN_POINT('',(-859.256317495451,494.538353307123,491.724435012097));
#1140=CARTESIAN_POINT('',(-855.469647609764,491.944884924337,498.283072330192));
#1141=CARTESIAN_POINT('',(-853.551787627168,490.681729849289,501.561416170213));
#1142=CARTESIAN_POINT('',(-849.667099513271,488.223137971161,508.114483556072));
#1143=CARTESIAN_POINT('',(-847.700271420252,487.027701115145,511.389207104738));
#1144=CARTESIAN_POINT('',(-843.723935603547,484.709031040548,517.923258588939));
#1145=CARTESIAN_POINT('',(-841.71457767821,483.585587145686,521.182602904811));
#1146=CARTESIAN_POINT('',(-837.647551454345,481.408104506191,527.694338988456));
#1147=CARTESIAN_POINT('',(-835.589883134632,480.354065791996,530.946730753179));
#1148=CARTESIAN_POINT('',(-831.426385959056,478.316817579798,537.443066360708));
#1149=CARTESIAN_POINT('',(-829.320555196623,477.333610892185,540.687009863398));
#1150=CARTESIAN_POINT('',(-825.061098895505,475.439798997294,547.164699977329));
#1151=CARTESIAN_POINT('',(-822.907473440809,474.529193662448,550.398446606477));
#1152=CARTESIAN_POINT('',(-818.554165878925,472.783119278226,556.852061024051));
#1153=CARTESIAN_POINT('',(-816.354514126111,471.947602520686,560.071936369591));
#1154=CARTESIAN_POINT('',(-811.908236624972,470.353268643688,566.49826318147));
#1155=CARTESIAN_POINT('',(-809.661610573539,469.594452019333,569.704714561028));
#1156=CARTESIAN_POINT('',(-805.122125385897,468.156056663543,576.102200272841));
#1157=CARTESIAN_POINT('',(-802.829270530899,467.476470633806,579.293235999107));
#1158=CARTESIAN_POINT('',(-798.197844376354,466.199189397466,585.658341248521));
#1159=CARTESIAN_POINT('',(-795.859274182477,465.601492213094,588.832411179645));
#1160=CARTESIAN_POINT('',(-790.425792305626,464.323621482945,596.115309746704));
#1161=CARTESIAN_POINT('',(-787.315253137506,463.67284026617,600.21769538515));
#1162=CARTESIAN_POINT('',(-781.020187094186,462.522039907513,608.386436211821));
#1163=CARTESIAN_POINT('',(-777.835663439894,462.022014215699,612.452792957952));
#1164=CARTESIAN_POINT('',(-771.394975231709,461.180501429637,620.545353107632));
#1165=CARTESIAN_POINT('',(-768.138807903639,460.839020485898,624.571554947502));
#1166=CARTESIAN_POINT('',(-761.558217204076,460.323168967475,632.578798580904));
#1167=CARTESIAN_POINT('',(-758.233793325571,460.148799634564,636.559840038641));
#1168=CARTESIAN_POINT('',(-751.524086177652,459.976505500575,644.467538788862));
#1169=CARTESIAN_POINT('',(-748.138866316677,459.978406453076,648.394245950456));
#1170=CARTESIAN_POINT('',(-741.309274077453,460.168124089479,656.191602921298));
#1171=CARTESIAN_POINT('',(-737.864900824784,460.355943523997,660.062251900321));
#1172=CARTESIAN_POINT('',(-730.923929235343,460.927984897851,667.740208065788));
#1173=CARTESIAN_POINT('',(-727.427343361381,461.312160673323,671.547529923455));
#1174=CARTESIAN_POINT('',(-720.388577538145,462.288022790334,679.092710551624));
#1175=CARTESIAN_POINT('',(-716.846400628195,462.879695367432,682.830573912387));
#1176=CARTESIAN_POINT('',(-710.647416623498,464.100550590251,689.271159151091));
#1177=CARTESIAN_POINT('',(-707.998874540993,464.680341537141,691.991278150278));
#1178=CARTESIAN_POINT('',(-702.685747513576,465.965136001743,697.385883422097));
#1179=CARTESIAN_POINT('',(-700.021163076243,466.670135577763,700.060371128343));
#1180=CARTESIAN_POINT('',(-694.680623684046,468.210313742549,705.360180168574));
#1181=CARTESIAN_POINT('',(-692.004668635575,469.045493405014,707.985501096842));
#1182=CARTESIAN_POINT('',(-686.646744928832,470.851020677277,713.183130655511));
#1183=CARTESIAN_POINT('',(-683.964776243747,471.821368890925,715.755439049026));
#1184=CARTESIAN_POINT('',(-678.603389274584,473.901210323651,720.840535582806));
#1185=CARTESIAN_POINT('',(-675.923970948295,475.010572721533,723.353377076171));
#1186=CARTESIAN_POINT('',(-670.571900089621,477.374004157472,728.317683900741));
#1187=CARTESIAN_POINT('',(-667.899247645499,478.628075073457,730.769148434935));
#1188=CARTESIAN_POINT('',(-662.568830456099,481.285277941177,735.605528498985));
#1189=CARTESIAN_POINT('',(-659.911062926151,482.688380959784,737.990456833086));
#1190=CARTESIAN_POINT('',(-654.618364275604,485.648135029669,742.689246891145));
#1191=CARTESIAN_POINT('',(-651.983431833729,487.204777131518,745.00311274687));
#1192=CARTESIAN_POINT('',(-647.333029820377,490.108692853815,749.044187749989));
#1193=CARTESIAN_POINT('',(-645.311151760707,491.424636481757,750.786594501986));
#1194=CARTESIAN_POINT('',(-641.291397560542,494.152832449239,754.223000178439));
#1195=CARTESIAN_POINT('',(-639.293520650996,495.565081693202,755.91700065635));
#1196=CARTESIAN_POINT('',(-635.326818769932,498.487196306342,759.253943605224));
#1197=CARTESIAN_POINT('',(-633.357992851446,499.997058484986,760.896887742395));
#1198=CARTESIAN_POINT('',(-629.454646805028,503.115494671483,764.129091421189));
#1199=CARTESIAN_POINT('',(-627.520126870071,504.72406923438,765.718350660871));
#1200=CARTESIAN_POINT('',(-623.692575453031,508.039302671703,768.83916652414));
#1201=CARTESIAN_POINT('',(-621.79951238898,509.745883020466,770.370767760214));
#1202=CARTESIAN_POINT('',(-618.059271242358,513.258543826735,773.374741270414));
#1203=CARTESIAN_POINT('',(-616.212092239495,515.064622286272,774.847114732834));
#1204=CARTESIAN_POINT('',(-612.569962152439,518.775978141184,777.729666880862));
#1205=CARTESIAN_POINT('',(-610.77500639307,520.681246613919,779.139851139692));
#1206=CARTESIAN_POINT('',(-607.243638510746,524.59043658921,781.895247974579));
#1207=CARTESIAN_POINT('',(-605.507224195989,526.594354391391,783.240462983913));
#1208=CARTESIAN_POINT('',(-602.367482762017,530.37686358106,785.656858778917));
#1209=CARTESIAN_POINT('',(-600.954707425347,532.141349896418,786.737872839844));
#1210=CARTESIAN_POINT('',(-598.179523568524,535.738446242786,788.849984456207));
#1211=CARTESIAN_POINT('',(-596.817113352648,537.571053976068,789.881083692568));
#1212=CARTESIAN_POINT('',(-594.146827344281,541.302932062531,791.891621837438));
#1213=CARTESIAN_POINT('',(-592.838948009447,543.20219807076,792.8710641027));
#1214=CARTESIAN_POINT('',(-590.281748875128,547.065812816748,794.776698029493));
#1215=CARTESIAN_POINT('',(-589.032429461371,549.030161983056,795.702889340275));
#1216=CARTESIAN_POINT('',(-586.596594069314,553.021689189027,797.500298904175));
#1217=CARTESIAN_POINT('',(-585.41007240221,555.048861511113,798.371522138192));
#1218=CARTESIAN_POINT('',(-583.103790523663,559.163784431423,800.057504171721));
#1219=CARTESIAN_POINT('',(-581.984030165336,561.251534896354,800.872263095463));
#1220=CARTESIAN_POINT('',(-579.815230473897,565.484908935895,802.44382488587));
#1221=CARTESIAN_POINT('',(-578.766193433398,567.630534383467,803.20062587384));
#1222=CARTESIAN_POINT('',(-576.742758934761,571.976454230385,804.65479704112));
#1223=CARTESIAN_POINT('',(-575.768361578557,574.176748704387,805.352167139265));
#1224=CARTESIAN_POINT('',(-573.892951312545,578.640356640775,806.689664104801));
#1225=CARTESIAN_POINT('',(-572.992356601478,580.903943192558,807.329466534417));
#1226=CARTESIAN_POINT('',(-571.273948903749,585.47892242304,808.546339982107));
#1227=CARTESIAN_POINT('',(-570.456136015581,587.790315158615,809.123410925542));
#1228=CARTESIAN_POINT('',(-568.906612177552,592.456719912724,810.213653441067));
#1229=CARTESIAN_POINT('',(-568.174903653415,594.811733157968,810.726823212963));
#1230=CARTESIAN_POINT('',(-566.800678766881,599.560739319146,811.688175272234));
#1231=CARTESIAN_POINT('',(-566.158162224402,601.954732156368,812.136357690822));
#1232=CARTESIAN_POINT('',(-564.965229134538,606.776173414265,812.966677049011));
#1233=CARTESIAN_POINT('',(-564.414787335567,609.203612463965,813.34883209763));
#1234=CARTESIAN_POINT('',(-563.408179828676,614.087481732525,814.046434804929));
#1235=CARTESIAN_POINT('',(-562.952014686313,616.543912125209,814.361882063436));
#1236=CARTESIAN_POINT('',(-562.1360106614,621.480195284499,814.92536554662));
#1237=CARTESIAN_POINT('',(-561.776164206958,623.960046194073,815.173407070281));
#1238=CARTESIAN_POINT('',(-561.154364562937,628.937789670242,815.601570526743));
#1239=CARTESIAN_POINT('',(-560.892409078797,631.43568181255,815.78169405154));
#1240=CARTESIAN_POINT('',(-560.487922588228,636.203776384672,816.059643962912));
#1241=CARTESIAN_POINT('',(-560.336351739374,638.472855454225,816.163703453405));
#1242=CARTESIAN_POINT('',(-560.114746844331,643.016838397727,816.315801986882));
#1243=CARTESIAN_POINT('',(-560.044711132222,645.291742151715,816.363842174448));
#1244=CARTESIAN_POINT('',(-559.986436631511,649.842938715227,816.403816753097));
#1245=CARTESIAN_POINT('',(-559.998192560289,652.11923142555,816.395754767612));
#1246=CARTESIAN_POINT('',(-560.103444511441,656.669047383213,816.323548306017));
#1247=CARTESIAN_POINT('',(-560.19694093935,658.942570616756,816.259403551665));
#1248=CARTESIAN_POINT('',(-560.465292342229,663.481941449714,816.075169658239));
#1249=CARTESIAN_POINT('',(-560.640126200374,665.747790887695,815.955095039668));
#1250=CARTESIAN_POINT('',(-561.070498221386,670.268154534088,815.659220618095));
#1251=CARTESIAN_POINT('',(-561.326036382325,672.52266874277,815.483420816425));
#1252=CARTESIAN_POINT('',(-561.916877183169,677.016182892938,815.076408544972));
#1253=CARTESIAN_POINT('',(-562.252179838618,679.2551828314,814.845196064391));
#1254=CARTESIAN_POINT('',(-563.001327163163,683.713587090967,814.327767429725));
#1255=CARTESIAN_POINT('',(-563.415171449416,685.932991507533,814.041551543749));
#1256=CARTESIAN_POINT('',(-564.306850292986,690.284533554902,813.423668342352));
#1257=CARTESIAN_POINT('',(-564.782493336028,692.417341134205,813.093551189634));
#1258=CARTESIAN_POINT('',(-565.804846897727,696.657272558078,812.382460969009));
#1259=CARTESIAN_POINT('',(-566.351557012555,698.764396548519,812.001488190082));
#1260=CARTESIAN_POINT('',(-567.514218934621,702.949565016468,811.18932072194));
#1261=CARTESIAN_POINT('',(-568.130168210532,705.027610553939,810.758127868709));
#1262=CARTESIAN_POINT('',(-569.429327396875,709.151550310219,809.84620198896));
#1263=CARTESIAN_POINT('',(-570.112537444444,711.197444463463,809.365468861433));
#1264=CARTESIAN_POINT('',(-571.54406192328,715.254155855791,808.355214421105));
#1265=CARTESIAN_POINT('',(-572.292377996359,717.264972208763,807.825691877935));
#1266=CARTESIAN_POINT('',(-573.85176958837,721.248693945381,806.718699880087));
#1267=CARTESIAN_POINT('',(-574.66284497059,723.221599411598,806.141230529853));
#1268=CARTESIAN_POINT('',(-576.345313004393,727.126976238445,804.939220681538));
#1269=CARTESIAN_POINT('',(-577.216706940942,729.059446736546,804.314679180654));
#1270=CARTESIAN_POINT('',(-579.017231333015,732.881575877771,803.01947400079));
#1271=CARTESIAN_POINT('',(-579.946362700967,734.771233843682,802.34880959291));
#1272=CARTESIAN_POINT('',(-581.907717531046,738.599317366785,800.927554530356));
#1273=CARTESIAN_POINT('',(-582.942774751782,740.535429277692,800.17464170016));
#1274=CARTESIAN_POINT('',(-585.07044576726,744.355831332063,798.620253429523));
#1275=CARTESIAN_POINT('',(-586.163060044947,746.2401210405,797.818777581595));
#1276=CARTESIAN_POINT('',(-588.402570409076,749.954861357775,796.168543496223));
#1277=CARTESIAN_POINT('',(-589.549464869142,751.785313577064,795.319786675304));
#1278=CARTESIAN_POINT('',(-591.89437841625,755.390879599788,793.576196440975));
#1279=CARTESIAN_POINT('',(-593.092401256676,757.165989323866,792.681359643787));
#1280=CARTESIAN_POINT('',(-595.536377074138,760.659542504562,790.846861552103));
#1281=CARTESIAN_POINT('',(-596.782336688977,762.377978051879,789.907194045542));
#1282=CARTESIAN_POINT('',(-599.318765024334,765.756762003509,787.984486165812));
#1283=CARTESIAN_POINT('',(-600.609234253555,767.417109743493,787.001445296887));
#1284=CARTESIAN_POINT('',(-603.231490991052,770.678845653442,784.99330922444));
#1285=CARTESIAN_POINT('',(-604.56328066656,772.280230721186,783.968211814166));
#1286=CARTESIAN_POINT('',(-607.2648426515,775.423159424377,781.877438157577));
#1287=CARTESIAN_POINT('',(-608.634613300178,776.964705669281,780.811763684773));
#1288=CARTESIAN_POINT('',(-611.580264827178,780.17406934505,778.507221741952));
#1289=CARTESIAN_POINT('',(-613.16072263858,781.833996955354,777.263209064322));
#1290=CARTESIAN_POINT('',(-616.361372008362,785.077416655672,774.727583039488));
#1291=CARTESIAN_POINT('',(-617.981564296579,786.660907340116,773.435968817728));
#1292=CARTESIAN_POINT('',(-621.257485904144,789.751333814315,770.807074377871));
#1293=CARTESIAN_POINT('',(-622.913214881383,791.258270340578,769.469794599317));
#1294=CARTESIAN_POINT('',(-626.256225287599,794.195806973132,766.751449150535));
#1295=CARTESIAN_POINT('',(-627.943508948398,795.626401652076,765.370380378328));
#1296=CARTESIAN_POINT('',(-633.048239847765,799.805301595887,761.163162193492));
#1297=CARTESIAN_POINT('',(-636.507580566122,802.439796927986,758.273790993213));
#1298=CARTESIAN_POINT('',(-643.508255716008,807.410114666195,752.341798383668));
#1299=CARTESIAN_POINT('',(-647.049600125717,809.745900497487,749.299158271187));
#1300=CARTESIAN_POINT('',(-653.352047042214,813.613744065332,743.803912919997));
#1301=CARTESIAN_POINT('',(-656.101590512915,815.205901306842,741.380056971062));
#1302=CARTESIAN_POINT('',(-661.623760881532,818.224679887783,736.456164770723));
#1303=CARTESIAN_POINT('',(-664.39638994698,819.651285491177,733.956121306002));
#1304=CARTESIAN_POINT('',(-669.956043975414,822.344158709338,728.884807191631));
#1305=CARTESIAN_POINT('',(-672.743073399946,823.610373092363,726.313513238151));
#1306=CARTESIAN_POINT('',(-678.322280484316,825.987211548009,721.105710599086));
#1307=CARTESIAN_POINT('',(-681.114458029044,827.097839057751,718.469203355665));
#1308=CARTESIAN_POINT('',(-686.700822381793,829.170598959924,713.131774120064));
#1309=CARTESIAN_POINT('',(-689.495005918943,830.132506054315,710.430761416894));
#1310=CARTESIAN_POINT('',(-695.074607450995,831.911449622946,704.972709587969));
#1311=CARTESIAN_POINT('',(-697.860025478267,832.728486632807,702.215670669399));
#1312=CARTESIAN_POINT('',(-703.416223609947,834.22330993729,696.649896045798));
#1313=CARTESIAN_POINT('',(-706.187004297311,834.901101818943,693.841162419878));
#1314=CARTESIAN_POINT('',(-711.709015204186,836.123070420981,688.175797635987));
#1315=CARTESIAN_POINT('',(-714.460244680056,836.66724208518,685.319164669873));
#1316=CARTESIAN_POINT('',(-721.079814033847,837.827428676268,678.36242330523));
#1317=CARTESIAN_POINT('',(-724.936131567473,838.378955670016,674.239989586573));
#1318=CARTESIAN_POINT('',(-732.589962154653,839.239856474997,665.91585438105));
#1319=CARTESIAN_POINT('',(-736.387470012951,839.549209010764,661.714145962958));
#1320=CARTESIAN_POINT('',(-743.916079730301,839.939986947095,653.23885723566));
#1321=CARTESIAN_POINT('',(-747.647158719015,840.021335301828,648.965253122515));
#1322=CARTESIAN_POINT('',(-755.034447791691,839.969202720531,640.355494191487));
#1323=CARTESIAN_POINT('',(-758.690659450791,839.835726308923,636.019340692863));
#1324=CARTESIAN_POINT('',(-765.931345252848,839.365746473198,627.280996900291));
#1325=CARTESIAN_POINT('',(-769.515626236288,839.02875671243,622.878673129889));
#1326=CARTESIAN_POINT('',(-776.598860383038,838.162778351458,614.024716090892));
#1327=CARTESIAN_POINT('',(-780.097813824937,837.633790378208,609.573082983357));
#1328=CARTESIAN_POINT('',(-787.006491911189,836.394299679,600.626939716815));
#1329=CARTESIAN_POINT('',(-790.416225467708,835.683815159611,596.13243390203));
#1330=CARTESIAN_POINT('',(-797.144227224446,834.090666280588,587.10541583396));
#1331=CARTESIAN_POINT('',(-800.462492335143,833.207996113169,582.572902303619));
#1332=CARTESIAN_POINT('',(-805.984306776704,831.579904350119,574.894909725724));
#1333=CARTESIAN_POINT('',(-808.212588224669,830.87760374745,571.757958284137));
#1334=CARTESIAN_POINT('',(-812.624304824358,829.39790926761,565.470148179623));
#1335=CARTESIAN_POINT('',(-814.807739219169,828.620514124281,562.319289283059));
#1336=CARTESIAN_POINT('',(-819.129382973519,826.99282547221,556.005118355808));
#1337=CARTESIAN_POINT('',(-821.267589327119,826.142527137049,552.841805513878));
#1338=CARTESIAN_POINT('',(-825.498255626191,824.37107709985,546.504478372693));
#1339=CARTESIAN_POINT('',(-827.590715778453,823.449925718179,543.330464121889));
#1340=CARTESIAN_POINT('',(-831.730723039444,821.538014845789,536.971513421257));
#1341=CARTESIAN_POINT('',(-833.778245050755,820.547217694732,533.786571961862));
#1342=CARTESIAN_POINT('',(-837.826953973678,818.497994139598,527.409007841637));
#1343=CARTESIAN_POINT('',(-839.828140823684,817.439567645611,524.216385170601));
#1344=CARTESIAN_POINT('',(-843.783902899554,815.256415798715,517.825114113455));
#1345=CARTESIAN_POINT('',(-845.738479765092,814.131692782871,514.626465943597));
#1346=CARTESIAN_POINT('',(-849.600921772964,811.816950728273,508.224605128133));
#1347=CARTESIAN_POINT('',(-851.508786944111,810.626931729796,505.021392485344));
#1348=CARTESIAN_POINT('',(-855.272710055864,808.185571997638,498.620436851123));
#1349=CARTESIAN_POINT('',(-857.128890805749,806.934400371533,495.422701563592));
#1350=CARTESIAN_POINT('',(-860.794496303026,804.368341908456,489.025994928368));
#1351=CARTESIAN_POINT('',(-862.603921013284,803.053455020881,485.827023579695));
#1352=CARTESIAN_POINT('',(-866.175967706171,800.360062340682,479.429468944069));
#1353=CARTESIAN_POINT('',(-867.938587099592,798.981553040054,476.230885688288));
#1354=CARTESIAN_POINT('',(-871.416756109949,796.160818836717,469.8362314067));
#1355=CARTESIAN_POINT('',(-873.132305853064,794.718594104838,466.640160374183));
#1356=CARTESIAN_POINT('',(-876.514934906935,791.770943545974,460.254943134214));
#1357=CARTESIAN_POINT('',(-878.18204820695,790.265563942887,457.065793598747));
#1358=CARTESIAN_POINT('',(-881.468875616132,787.189653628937,450.694431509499));
#1359=CARTESIAN_POINT('',(-883.088589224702,785.619122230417,447.512219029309));
#1360=CARTESIAN_POINT('',(-886.280068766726,782.411708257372,441.157884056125));
#1361=CARTESIAN_POINT('',(-887.851841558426,780.77483525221,437.985760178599));
#1362=CARTESIAN_POINT('',(-890.947250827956,777.432573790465,431.654273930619));
#1363=CARTESIAN_POINT('',(-892.470889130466,775.727187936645,428.494911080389));
#1364=CARTESIAN_POINT('',(-894.994814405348,772.796451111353,423.19022949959));
#1365=CARTESIAN_POINT('',(-896.008060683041,771.590076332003,421.040569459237));
#1366=CARTESIAN_POINT('',(-898.011621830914,769.143025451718,416.750203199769));
#1367=CARTESIAN_POINT('',(-899.001937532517,767.902350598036,414.609496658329));
#1368=CARTESIAN_POINT('',(-900.959358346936,765.385499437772,410.338582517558));
#1369=CARTESIAN_POINT('',(-901.926465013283,764.109325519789,408.208374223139));
#1370=CARTESIAN_POINT('',(-903.837248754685,761.519908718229,403.959964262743));
#1371=CARTESIAN_POINT('',(-904.780925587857,760.206665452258,401.841762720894));
#1372=CARTESIAN_POINT('',(-906.646060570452,757.53913198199,397.615724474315));
#1373=CARTESIAN_POINT('',(-907.567478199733,756.18477576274,395.507911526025));
#1374=CARTESIAN_POINT('',(-909.385981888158,753.435128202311,391.308537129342));
#1375=CARTESIAN_POINT('',(-910.283067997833,752.039836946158,389.216975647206));
#1376=CARTESIAN_POINT('',(-912.052321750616,749.206023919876,385.052826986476));
#1377=CARTESIAN_POINT('',(-912.924490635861,747.767504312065,382.980238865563));
#1378=CARTESIAN_POINT('',(-914.643287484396,744.844413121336,378.857024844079));
#1379=CARTESIAN_POINT('',(-915.489915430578,743.359841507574,376.806398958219));
#1380=CARTESIAN_POINT('',(-917.163754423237,740.328852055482,372.71379870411));
#1381=CARTESIAN_POINT('',(-917.990744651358,738.782021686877,370.672039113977));
#1382=CARTESIAN_POINT('',(-919.616867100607,735.634435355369,366.619128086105));
#1383=CARTESIAN_POINT('',(-920.41599910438,734.033678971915,364.607976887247));
#1384=CARTESIAN_POINT('',(-921.985507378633,730.772899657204,360.620738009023));
#1385=CARTESIAN_POINT('',(-922.755867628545,729.112844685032,358.644670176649));
#1386=CARTESIAN_POINT('',(-924.265684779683,725.729146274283,354.735582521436));
#1387=CARTESIAN_POINT('',(-925.005142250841,724.005504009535,352.802561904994));
#1388=CARTESIAN_POINT('',(-926.449001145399,720.493579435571,348.99338773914));
#1389=CARTESIAN_POINT('',(-927.153495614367,718.705493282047,347.117089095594));
#1390=CARTESIAN_POINT('',(-928.527014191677,715.053151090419,343.426063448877));
#1391=CARTESIAN_POINT('',(-929.196035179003,713.188888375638,341.611341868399));
#1392=CARTESIAN_POINT('',(-930.49433541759,709.37879620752,338.058964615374));
#1393=CARTESIAN_POINT('',(-931.123657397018,707.433058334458,336.321226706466));
#1394=CARTESIAN_POINT('',(-932.338693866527,703.450300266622,332.938114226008));
#1395=CARTESIAN_POINT('',(-932.924420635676,701.41330603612,331.292713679));
#1396=CARTESIAN_POINT('',(-933.980645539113,697.484303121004,328.302247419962));
#1397=CARTESIAN_POINT('',(-934.456597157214,695.603369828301,326.944606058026));
#1398=CARTESIAN_POINT('',(-935.365024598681,691.757766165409,324.336518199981));
#1399=CARTESIAN_POINT('',(-935.79749724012,689.793089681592,323.086079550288));
#1400=CARTESIAN_POINT('',(-936.611788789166,685.780210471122,320.71782351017));
#1401=CARTESIAN_POINT('',(-936.993706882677,683.732181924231,319.599746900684));
#1402=CARTESIAN_POINT('',(-937.700274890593,679.548305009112,317.520708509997));
#1403=CARTESIAN_POINT('',(-938.024946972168,677.412491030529,316.559685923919));
#1404=CARTESIAN_POINT('',(-938.516079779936,673.747443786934,315.099920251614));
#1405=CARTESIAN_POINT('',(-938.700077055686,672.240400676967,314.551177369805));
#1406=CARTESIAN_POINT('',(-939.034578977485,669.190621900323,313.55117219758));
#1407=CARTESIAN_POINT('',(-939.185088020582,667.647890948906,313.099897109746));
#1408=CARTESIAN_POINT('',(-939.449857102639,664.532511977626,312.304566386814));
#1409=CARTESIAN_POINT('',(-939.564132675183,662.95987708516,311.960464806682));
#1410=CARTESIAN_POINT('',(-939.754188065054,659.791200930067,311.387471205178));
#1411=CARTESIAN_POINT('',(-939.829964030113,658.195157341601,311.158590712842));
#1412=CARTESIAN_POINT('',(-939.885615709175,656.59188491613,310.990400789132));
#1413=B_SPLINE_CURVE_WITH_KNOTS('',3,(#1067,#1068,#1069,#1070,#1071,#1072,#1073,#1074,#1075,
#1076,#1077,#1078,#1079,#1080,#1081,#1082,#1083,#1084,#1085,#1086,#1087,#1088,#1089,#1090,#1091,
#1092,#1093,#1094,#1095,#1096,#1097,#1098,#1099,#1100,#1101,#1102,#1103,#1104,#1105,#1106,#1107,
#1108,#1109,#1110,#1111,#1112,#1113,#1114,#1115,#1116,#1117,#1118,#1119,#1120,#1121,#1122,#1123,
#1124,#1125,#1126,#1127,#1128,#1129,#1130,#1131,#1132,#1133,#1134,#1135,#1136,#1137,#1138,#1139,
#1140,#1141,#1142,#1143,#1144,#1145,#1146,#1147,#1148,#1149,#1150,#1151,#1152,#1153,#1154,#1155,
#1156,#1157,#1158,#1159,#1160,#1161,#1162,#1163,#1164,#1165,#1166,#1167,#1168,#1169,#1170,#1171,
#1172,#1173,#1174,#1175,#1176,#1177,#1178,#1179,#1180,#1181,#1182,#1183,#1184,#1185,#1186,#1187,
#1188,#1189,#1190,#1191,#1192,#1193,#1194,#1195,#1196,#1197,#1198,#1199,#1200,#1201,#1202,#1203,
#1204,#1205,#1206,#1207,#1208,#1209,#1210,#1211,#1212,#1213,#1214,#1215,#1216,#1217,#1218,#1219,
#1220,#1221,#1222,#1223,#1224,#1225,#1226,#1227,#1228,#1229,#1230,#1231,#1232,#1233,#1234,#1235,
#1236,#1237,#1238,#1239,#1240,#1241,#1242,#1243,#1244,#1245,#1246,#1247,#1248,#1249,#1250,#1251,
#1252,#1253,#1254,#1255,#1256,#1257,#1258,#1259,#1260,#1261,#1262,#1263,#1264,#1265,#1266,#1267,
#1268,#1269,#1270,#1271,#1272,#1273,#1274,#1275,#1276,#1277,#1278,#1279,#1280,#1281,#1282,#1283,
#1284,#1285,#1286,#1287,#1288,#1289,#1290,#1291,#1292,#1293,#1294,#1295,#1296,#1297,#1298,#1299,
#1300,#1301,#1302,#1303,#1304,#1305,#1306,#1307,#1308,#1309,#1310,#1311,#1312,#1313,#1314,#1315,
#1316,#1317,#1318,#1319,#1320,#1321,#1322,#1323,#1324,#1325,#1326,#1327,#1328,#1329,#1330,#1331,
#1332,#1333,#1334,#1335,#1336,#1337,#1338,#1339,#1340,#1341,#1342,#1343,#1344,#1345,#1346,#1347,
#1348,#1349,#1350,#1351,#1352,#1353,#1354,#1355,#1356,#1357,#1358,#1359,#1360,#1361,#1362,#1363,
#1364,#1365,#1366,#1367,#1368,#1369,#1370,#1371,#1372,#1373,#1374,#1375,#1376,#1377,#1378,#1379,
#1380,#1381,#1382,#1383,#1384,#1385,#1386,#1387,#1388,#1389,#1390,#1391,#1392,#1393,#1394,#1395,
#1396,#1397,#1398,#1399,#1400,#1401,#1402,#1403,#1404,#1405,#1406,#1407,#1408,#1409,#1410,#1411,
#1412),.UNSPECIFIED.,.T.,.F.,(4,2,2,2,2,2,2,2,2,2,2,2,2,2,2,2,2,2,2,2,2,2,2,2,2,2,2,2,2,2,2,2,2,
2,2,2,2,2,2,2,2,2,2,2,2,2,2,2,2,2,2,2,2,2,2,2,2,2,2,2,2,2,2,2,2,2,2,2,2,2,2,2,2,2,2,2,2,2,2,2,2,
2,2,2,2,2,2,2,2,2,2,2,2,2,2,2,2,2,2,2,2,2,2,2,2,2,2,2,2,2,2,2,2,2,2,2,2,2,2,2,2,2,2,2,2,2,2,2,2,
2,2,2,2,2,2,2,2,2,2,2,2,2,2,2,2,2,2,2,2,2,2,2,2,2,2,2,2,2,2,2,2,2,2,2,2,2,2,2,2,2,2,2,4),(0.,
5.54218418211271,11.084721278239,16.6306841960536,22.1768371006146,27.6757642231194,
33.1746670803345,38.675712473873,44.1772901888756,49.3900146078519,54.603699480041,
59.8210220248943,65.0380927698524,70.2736474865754,75.5092108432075,80.7429645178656,
85.976859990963,93.250853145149,100.525563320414,107.803001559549,115.080228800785,
122.369252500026,129.658324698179,136.946156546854,144.233971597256,151.55432885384,
158.874688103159,166.195110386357,173.515644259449,188.144522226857,202.773812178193,
214.771126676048,226.768708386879,238.767359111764,250.765934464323,262.773490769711,
274.781067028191,286.788178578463,298.7952807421,310.765469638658,322.735663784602,
334.706332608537,346.67698039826,358.639967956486,370.603032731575,382.564994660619,
394.526667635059,410.091638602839,425.655933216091,441.220831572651,456.785845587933,
472.33547346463,487.885331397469,503.431535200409,518.976707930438,530.496286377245,
542.015502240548,553.534813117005,565.054175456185,576.562777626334,588.071529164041,
599.578050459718,611.083901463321,620.009556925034,628.934925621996,637.860002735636,
646.785130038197,655.703203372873,664.6210976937,673.538191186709,682.45495045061,
689.969865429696,697.484527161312,704.99869997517,712.512922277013,720.02646270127,
727.539986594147,735.053753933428,742.5675315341,750.121301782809,757.675081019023,
765.229073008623,772.783049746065,780.334951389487,787.886898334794,795.43825142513,
802.989427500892,809.816861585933,816.644156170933,823.471009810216,830.297897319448,
837.123013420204,843.948129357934,850.773246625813,857.598330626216,864.226437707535,
870.854507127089,877.482334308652,884.110175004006,890.738182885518,897.366176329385,
903.994311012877,910.622550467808,917.583516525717,924.54454100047,931.505357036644,
938.466684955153,945.428980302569,952.391355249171,959.354095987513,966.316532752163,
974.138071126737,981.959753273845,989.781360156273,997.603522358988,1013.25253620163,
1028.90346432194,1040.88805054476,1052.8737749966,1064.86346698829,1076.85289406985,
1088.86030974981,1100.86768103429,1112.87457044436,1124.88191412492,1141.89069319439,
1158.90096634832,1175.91698682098,1192.93264892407,1209.98913521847,1227.04556581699,
1244.10028609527,1261.15558172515,1272.88880437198,1284.62222488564,1296.35642278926,
1308.09056763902,1319.83110717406,1331.57166231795,1343.31180383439,1355.05193810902,
1366.76126529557,1378.47060178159,1390.18058466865,1401.89053616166,1413.59206160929,
1425.29371059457,1436.99367765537,1448.69320066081,1456.68836349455,1464.68323598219,
1472.67757181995,1480.67199015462,1488.68000565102,1496.68800451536,1504.69560347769,
1512.70320780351,1520.77759404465,1528.85204326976,1536.9309234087,1545.00965448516,
1553.06558575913,1561.12222463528,1569.17003872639,1577.21557741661,1584.31605608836,
1591.41705401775,1598.50390679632,1605.58800930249,1610.42786955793,1615.26709395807,
1620.10424092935,1624.94187180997),.UNSPECIFIED.);
#1414=CARTESIAN_POINT('',(-939.885615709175,656.59188491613,310.990400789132));
#1415=VERTEX_POINT('',#1414);
#1416=EDGE_CURVE('E336',#1415,#1415,#1413,.T.);
#1417=ORIENTED_EDGE('',*,*,#1416,.T.);
#1418=EDGE_LOOP('',(#1417));
#1419=FACE_BOUND('',#1418,.T.);
#1420=CARTESIAN_POINT('',(0.,990.,0.));
#1421=DIRECTION('',(0.,1.,0.));
#1422=DIRECTION('',(0.,0.,1.));
#1423=AXIS2_PLACEMENT_3D('',#1420,#1421,#1422);
#1424=CIRCLE('',#1423,990.);
#1425=CARTESIAN_POINT('',(0.,990.,990.));
#1426=VERTEX_POINT('',#1425);
#1427=EDGE_CURVE('E322',#1426,#1426,#1424,.T.);
#1428=ORIENTED_EDGE('',*,*,#1427,.T.);
#1429=EDGE_LOOP('',(#1428));
#1430=FACE_BOUND('',#1429,.T.);
#1431=CARTESIAN_POINT('',(0.,10.,0.));
#1432=DIRECTION('',(0.,1.,0.));
#1433=DIRECTION('',(0.,0.,1.));
#1434=AXIS2_PLACEMENT_3D('',#1431,#1432,#1433);
#1435=CIRCLE('',#1434,990.);
#1436=CARTESIAN_POINT('',(0.,10.,990.));
#1437=VERTEX_POINT('',#1436);
#1438=EDGE_CURVE('E323',#1437,#1437,#1435,.T.);
#1439=ORIENTED_EDGE('',*,*,#1438,.F.);
#1440=EDGE_LOOP('',(#1439));
#1441=FACE_BOUND('',#1440,.T.);
#1442=CARTESIAN_POINT('',(939.885615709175,306.59188491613,-310.990400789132));
#1443=CARTESIAN_POINT('',(939.949372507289,304.755111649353,-310.797715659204));
#1444=CARTESIAN_POINT('',(939.986716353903,302.908850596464,-310.684686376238));
#1445=CARTESIAN_POINT('',(940.007358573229,299.213181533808,-310.622225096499));
#1446=CARTESIAN_POINT('',(939.990653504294,297.363773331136,-310.672803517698));
#1447=CARTESIAN_POINT('',(939.903709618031,293.676713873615,-310.935741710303));
#1448=CARTESIAN_POINT('',(939.833437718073,291.839070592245,-311.148201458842));
#1449=CARTESIAN_POINT('',(939.641474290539,288.191173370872,-311.727432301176));
#1450=CARTESIAN_POINT('',(939.519781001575,286.380920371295,-312.09420868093));
#1451=CARTESIAN_POINT('',(939.229597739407,282.814724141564,-312.966405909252));
#1452=CARTESIAN_POINT('',(939.061515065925,281.058449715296,-313.470619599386));
#1453=CARTESIAN_POINT('',(938.682088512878,277.592185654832,-314.604980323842));
#1454=CARTESIAN_POINT('',(938.470744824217,275.882195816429,-315.235126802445));
#1455=CARTESIAN_POINT('',(938.008859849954,272.512501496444,-316.606857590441));
#1456=CARTESIAN_POINT('',(937.758303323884,270.852816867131,-317.348485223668));
#1457=CARTESIAN_POINT('',(937.222030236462,267.586242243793,-318.928772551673));
#1458=CARTESIAN_POINT('',(936.936310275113,265.979357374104,-319.76744162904));
#1459=CARTESIAN_POINT('',(936.349217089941,262.901572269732,-321.482381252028));
#1460=CARTESIAN_POINT('',(936.049453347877,261.427961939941,-322.354365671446));
#1461=CARTESIAN_POINT('',(935.424338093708,258.526911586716,-324.163884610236));
#1462=CARTESIAN_POINT('',(935.098981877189,257.099480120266,-325.101431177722));
#1463=CARTESIAN_POINT('',(934.424876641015,254.288342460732,-327.033940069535));
#1464=CARTESIAN_POINT('',(934.076111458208,252.904667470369,-328.028941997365));
#1465=CARTESIAN_POINT('',(933.357447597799,250.180010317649,-330.068241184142));
#1466=CARTESIAN_POINT('',(932.987549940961,248.839026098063,-331.112536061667));
#1467=CARTESIAN_POINT('',(932.226992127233,246.192701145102,-333.247842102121));
#1468=CARTESIAN_POINT('',(931.836263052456,244.887503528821,-334.339005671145));
#1469=CARTESIAN_POINT('',(931.036728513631,242.315368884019,-336.559062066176));
#1470=CARTESIAN_POINT('',(930.627923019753,241.048431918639,-337.687954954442));
#1471=CARTESIAN_POINT('',(929.793627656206,238.550962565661,-339.978374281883));
#1472=CARTESIAN_POINT('',(929.368143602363,237.320417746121,-341.139889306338));
#1473=CARTESIAN_POINT('',(928.501402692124,234.893089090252,-343.491945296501));
#1474=CARTESIAN_POINT('',(928.060145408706,233.696306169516,-344.682487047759));
#1475=CARTESIAN_POINT('',(926.987850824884,230.874142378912,-347.558209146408));
#1476=CARTESIAN_POINT('',(926.349881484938,229.26353085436,-349.255310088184));
#1477=CARTESIAN_POINT('',(925.047142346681,226.09853621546,-352.691311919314));
#1478=CARTESIAN_POINT('',(924.382369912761,224.544158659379,-354.430216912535));
#1479=CARTESIAN_POINT('',(923.027383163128,221.486807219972,-357.944125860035));
#1480=CARTESIAN_POINT('',(922.33715940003,219.983852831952,-359.719143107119));
#1481=CARTESIAN_POINT('',(920.932791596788,217.026145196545,-363.299451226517));
#1482=CARTESIAN_POINT('',(920.218648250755,215.571390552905,-365.104741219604));
#1483=CARTESIAN_POINT('',(918.766266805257,212.704332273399,-368.744345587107));
#1484=CARTESIAN_POINT('',(918.027991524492,211.292101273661,-370.578702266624));
#1485=CARTESIAN_POINT('',(916.52927956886,208.509584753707,-374.270020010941));
#1486=CARTESIAN_POINT('',(915.768842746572,207.139299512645,-376.126981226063));
#1487=CARTESIAN_POINT('',(914.226628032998,204.438331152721,-379.860172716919));
#1488=CARTESIAN_POINT('',(913.444853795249,203.107641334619,-381.736399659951));
#1489=CARTESIAN_POINT('',(911.860405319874,200.483376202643,-385.505876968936));
#1490=CARTESIAN_POINT('',(911.057731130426,199.189800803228,-387.399127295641));
#1491=CARTESIAN_POINT('',(909.428316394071,196.632106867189,-391.208958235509));
#1492=CARTESIAN_POINT('',(908.601484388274,195.368145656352,-393.125605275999));
#1493=CARTESIAN_POINT('',(906.927592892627,192.873970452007,-396.971964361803));
#1494=CARTESIAN_POINT('',(906.08053339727,191.643756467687,-398.901676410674));
#1495=CARTESIAN_POINT('',(904.366503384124,189.215564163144,-402.772526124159));
#1496=CARTESIAN_POINT('',(903.499532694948,188.017586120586,-404.713663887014));
#1497=CARTESIAN_POINT('',(901.745953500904,185.652581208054,-408.605913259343));
#1498=CARTESIAN_POINT('',(900.859344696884,184.485554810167,-410.557025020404));
#1499=CARTESIAN_POINT('',(898.171871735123,181.031057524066,-416.42017492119));
#1500=CARTESIAN_POINT('',(896.341933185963,178.788150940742,-420.345254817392));
#1501=CARTESIAN_POINT('',(892.60597111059,174.414141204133,-428.221416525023));
#1502=CARTESIAN_POINT('',(890.699945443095,172.283041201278,-432.172499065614));
#1503=CARTESIAN_POINT('',(887.162505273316,168.501370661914,-439.381134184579));
#1504=CARTESIAN_POINT('',(885.543379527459,166.833327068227,-442.635571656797));
#1505=CARTESIAN_POINT('',(882.254985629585,163.566903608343,-449.154168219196));
#1506=CARTESIAN_POINT('',(880.585716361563,161.968525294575,-452.418327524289));
#1507=CARTESIAN_POINT('',(877.197232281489,158.839871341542,-458.953772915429));
#1508=CARTESIAN_POINT('',(875.47801303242,157.309601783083,-462.225059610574));
#1509=CARTESIAN_POINT('',(871.990019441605,154.316382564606,-468.771973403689));
#1510=CARTESIAN_POINT('',(870.221245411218,152.853432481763,-472.047600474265));
#1511=CARTESIAN_POINT('',(866.632983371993,149.99328331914,-478.603433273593));
#1512=CARTESIAN_POINT('',(864.813458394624,148.596134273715,-481.883640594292));
#1513=CARTESIAN_POINT('',(861.125125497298,145.868669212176,-488.444141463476));
#1514=CARTESIAN_POINT('',(859.256317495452,144.538353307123,-491.724435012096));
#1515=CARTESIAN_POINT('',(855.469647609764,141.944884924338,-498.28307233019));
#1516=CARTESIAN_POINT('',(853.551787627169,140.681729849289,-501.561416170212));
#1517=CARTESIAN_POINT('',(849.667099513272,138.223137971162,-508.114483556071));
#1518=CARTESIAN_POINT('',(847.700271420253,137.027701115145,-511.389207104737));
#1519=CARTESIAN_POINT('',(843.723935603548,134.709031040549,-517.923258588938));
#1520=CARTESIAN_POINT('',(841.714577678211,133.585587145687,-521.18260290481));
#1521=CARTESIAN_POINT('',(837.647551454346,131.408104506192,-527.694338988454));
#1522=CARTESIAN_POINT('',(835.589883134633,130.354065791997,-530.946730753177));
#1523=CARTESIAN_POINT('',(831.426385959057,128.316817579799,-537.443066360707));
#1524=CARTESIAN_POINT('',(829.320555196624,127.333610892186,-540.687009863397));
#1525=CARTESIAN_POINT('',(825.061098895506,125.439798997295,-547.164699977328));
#1526=CARTESIAN_POINT('',(822.90747344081,124.529193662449,-550.398446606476));
#1527=CARTESIAN_POINT('',(818.554165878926,122.783119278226,-556.852061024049));
#1528=CARTESIAN_POINT('',(816.354514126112,121.947602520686,-560.07193636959));
#1529=CARTESIAN_POINT('',(811.908236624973,120.353268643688,-566.498263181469));
#1530=CARTESIAN_POINT('',(809.66161057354,119.594452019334,-569.704714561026));
#1531=CARTESIAN_POINT('',(805.122125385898,118.156056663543,-576.10220027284));
#1532=CARTESIAN_POINT('',(802.8292705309,117.476470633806,-579.293235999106));
#1533=CARTESIAN_POINT('',(798.197844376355,116.199189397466,-585.65834124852));
#1534=CARTESIAN_POINT('',(795.859274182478,115.601492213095,-588.832411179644));
#1535=CARTESIAN_POINT('',(790.425792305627,114.323621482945,-596.115309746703));
#1536=CARTESIAN_POINT('',(787.315253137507,113.672840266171,-600.217695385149));
#1537=CARTESIAN_POINT('',(781.020187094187,112.522039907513,-608.386436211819));
#1538=CARTESIAN_POINT('',(777.835663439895,112.022014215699,-612.452792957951));
#1539=CARTESIAN_POINT('',(771.39497523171,111.180501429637,-620.545353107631));
#1540=CARTESIAN_POINT('',(768.13880790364,110.839020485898,-624.571554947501));
#1541=CARTESIAN_POINT('',(761.558217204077,110.323168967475,-632.578798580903));
#1542=CARTESIAN_POINT('',(758.233793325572,110.148799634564,-636.55984003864));
#1543=CARTESIAN_POINT('',(751.524086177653,109.976505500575,-644.467538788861));
#1544=CARTESIAN_POINT('',(748.138866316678,109.978406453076,-648.394245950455));
#1545=CARTESIAN_POINT('',(741.309274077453,110.168124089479,-656.191602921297));
#1546=CARTESIAN_POINT('',(737.864900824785,110.355943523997,-660.06225190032));
#1547=CARTESIAN_POINT('',(730.923929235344,110.927984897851,-667.740208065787));
#1548=CARTESIAN_POINT('',(727.427343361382,111.312160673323,-671.547529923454));
#1549=CARTESIAN_POINT('',(720.388577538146,112.288022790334,-679.092710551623));
#1550=CARTESIAN_POINT('',(716.846400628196,112.879695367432,-682.830573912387));
#1551=CARTESIAN_POINT('',(710.647416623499,114.100550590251,-689.27115915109));
#1552=CARTESIAN_POINT('',(707.998874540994,114.680341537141,-691.991278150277));
#1553=CARTESIAN_POINT('',(702.685747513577,115.965136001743,-697.385883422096));
#1554=CARTESIAN_POINT('',(700.021163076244,116.670135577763,-700.060371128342));
#1555=CARTESIAN_POINT('',(694.680623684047,118.210313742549,-705.360180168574));
#1556=CARTESIAN_POINT('',(692.004668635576,119.045493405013,-707.985501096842));
#1557=CARTESIAN_POINT('',(686.646744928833,120.851020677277,-713.18313065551));
#1558=CARTESIAN_POINT('',(683.964776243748,121.821368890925,-715.755439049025));
#1559=CARTESIAN_POINT('',(678.603389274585,123.901210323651,-720.840535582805));
#1560=CARTESIAN_POINT('',(675.923970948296,125.010572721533,-723.35337707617));
#1561=CARTESIAN_POINT('',(670.571900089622,127.374004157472,-728.31768390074));
#1562=CARTESIAN_POINT('',(667.8992476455,128.628075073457,-730.769148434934));
#1563=CARTESIAN_POINT('',(662.5688304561,131.285277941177,-735.605528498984));
#1564=CARTESIAN_POINT('',(659.911062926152,132.688380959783,-737.990456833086));
#1565=CARTESIAN_POINT('',(654.618364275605,135.648135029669,-742.689246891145));
#1566=CARTESIAN_POINT('',(651.98343183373,137.204777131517,-745.003112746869));
#1567=CARTESIAN_POINT('',(647.333029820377,140.108692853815,-749.044187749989));
#1568=CARTESIAN_POINT('',(645.311151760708,141.424636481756,-750.786594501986));
#1569=CARTESIAN_POINT('',(641.291397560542,144.152832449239,-754.223000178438));
#1570=CARTESIAN_POINT('',(639.293520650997,145.565081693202,-755.917000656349));
#1571=CARTESIAN_POINT('',(635.326818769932,148.487196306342,-759.253943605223));
#1572=CARTESIAN_POINT('',(633.357992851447,149.997058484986,-760.896887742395));
#1573=CARTESIAN_POINT('',(629.454646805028,153.115494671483,-764.129091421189));
#1574=CARTESIAN_POINT('',(627.520126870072,154.724069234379,-765.718350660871));
#1575=CARTESIAN_POINT('',(623.692575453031,158.039302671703,-768.83916652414));
#1576=CARTESIAN_POINT('',(621.79951238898,159.745883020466,-770.370767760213));
#1577=CARTESIAN_POINT('',(618.059271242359,163.258543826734,-773.374741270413));
#1578=CARTESIAN_POINT('',(616.212092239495,165.064622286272,-774.847114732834));
#1579=CARTESIAN_POINT('',(612.569962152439,168.775978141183,-777.729666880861));
#1580=CARTESIAN_POINT('',(610.77500639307,170.681246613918,-779.139851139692));
#1581=CARTESIAN_POINT('',(607.243638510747,174.590436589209,-781.895247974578));
#1582=CARTESIAN_POINT('',(605.50722419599,176.59435439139,-783.240462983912));
#1583=CARTESIAN_POINT('',(602.367482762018,180.376863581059,-785.656858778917));
#1584=CARTESIAN_POINT('',(600.954707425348,182.141349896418,-786.737872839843));
#1585=CARTESIAN_POINT('',(598.179523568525,185.738446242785,-788.849984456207));
#1586=CARTESIAN_POINT('',(596.817113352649,187.571053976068,-789.881083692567));
#1587=CARTESIAN_POINT('',(594.146827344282,191.302932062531,-791.891621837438));
#1588=CARTESIAN_POINT('',(592.838948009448,193.20219807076,-792.8710641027));
#1589=CARTESIAN_POINT('',(590.281748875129,197.065812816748,-794.776698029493));
#1590=CARTESIAN_POINT('',(589.032429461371,199.030161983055,-795.702889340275));
#1591=CARTESIAN_POINT('',(586.596594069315,203.021689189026,-797.500298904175));
#1592=CARTESIAN_POINT('',(585.41007240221,205.048861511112,-798.371522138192));
#1593=CARTESIAN_POINT('',(583.103790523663,209.163784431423,-800.057504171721));
#1594=CARTESIAN_POINT('',(581.984030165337,211.251534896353,-800.872263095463));
#1595=CARTESIAN_POINT('',(579.815230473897,215.484908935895,-802.44382488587));
#1596=CARTESIAN_POINT('',(578.766193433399,217.630534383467,-803.20062587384));
#1597=CARTESIAN_POINT('',(576.742758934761,221.976454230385,-804.65479704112));
#1598=CARTESIAN_POINT('',(575.768361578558,224.176748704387,-805.352167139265));
#1599=CARTESIAN_POINT('',(573.892951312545,228.640356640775,-806.689664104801));
#1600=CARTESIAN_POINT('',(572.992356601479,230.903943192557,-807.329466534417));
#1601=CARTESIAN_POINT('',(571.273948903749,235.478922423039,-808.546339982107));
#1602=CARTESIAN_POINT('',(570.456136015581,237.790315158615,-809.123410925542));
#1603=CARTESIAN_POINT('',(568.906612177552,242.456719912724,-810.213653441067));
#1604=CARTESIAN_POINT('',(568.174903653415,244.811733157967,-810.726823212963));
#1605=CARTESIAN_POINT('',(566.800678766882,249.560739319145,-811.688175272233));
#1606=CARTESIAN_POINT('',(566.158162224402,251.954732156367,-812.136357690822));
#1607=CARTESIAN_POINT('',(564.965229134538,256.776173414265,-812.966677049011));
#1608=CARTESIAN_POINT('',(564.414787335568,259.203612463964,-813.34883209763));
#1609=CARTESIAN_POINT('',(563.408179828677,264.087481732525,-814.046434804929));
#1610=CARTESIAN_POINT('',(562.952014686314,266.543912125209,-814.361882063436));
#1611=CARTESIAN_POINT('',(562.1360106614,271.480195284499,-814.92536554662));
#1612=CARTESIAN_POINT('',(561.776164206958,273.960046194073,-815.173407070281));
#1613=CARTESIAN_POINT('',(561.154364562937,278.937789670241,-815.601570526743));
#1614=CARTESIAN_POINT('',(560.892409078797,281.43568181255,-815.78169405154));
#1615=CARTESIAN_POINT('',(560.487922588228,286.203776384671,-816.059643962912));
#1616=CARTESIAN_POINT('',(560.336351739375,288.472855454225,-816.163703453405));
#1617=CARTESIAN_POINT('',(560.114746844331,293.016838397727,-816.315801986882));
#1618=CARTESIAN_POINT('',(560.044711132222,295.291742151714,-816.363842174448));
#1619=CARTESIAN_POINT('',(559.986436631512,299.842938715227,-816.403816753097));
#1620=CARTESIAN_POINT('',(559.998192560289,302.11923142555,-816.395754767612));
#1621=CARTESIAN_POINT('',(560.103444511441,306.669047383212,-816.323548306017));
#1622=CARTESIAN_POINT('',(560.19694093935,308.942570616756,-816.259403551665));
#1623=CARTESIAN_POINT('',(560.465292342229,313.481941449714,-816.075169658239));
#1624=CARTESIAN_POINT('',(560.640126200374,315.747790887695,-815.955095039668));
#1625=CARTESIAN_POINT('',(561.070498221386,320.268154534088,-815.659220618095));
#1626=CARTESIAN_POINT('',(561.326036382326,322.52266874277,-815.483420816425));
#1627=CARTESIAN_POINT('',(561.916877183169,327.016182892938,-815.076408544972));
#1628=CARTESIAN_POINT('',(562.252179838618,329.2551828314,-814.845196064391));
#1629=CARTESIAN_POINT('',(563.001327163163,333.713587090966,-814.327767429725));
#1630=CARTESIAN_POINT('',(563.415171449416,335.932991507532,-814.041551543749));
#1631=CARTESIAN_POINT('',(564.306850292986,340.284533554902,-813.423668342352));
#1632=CARTESIAN_POINT('',(564.782493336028,342.417341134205,-813.093551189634));
#1633=CARTESIAN_POINT('',(565.804846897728,346.657272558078,-812.382460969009));
#1634=CARTESIAN_POINT('',(566.351557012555,348.764396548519,-812.001488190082));
#1635=CARTESIAN_POINT('',(567.514218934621,352.949565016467,-811.18932072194));
#1636=CARTESIAN_POINT('',(568.130168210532,355.027610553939,-810.758127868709));
#1637=CARTESIAN_POINT('',(569.429327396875,359.151550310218,-809.846201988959));
#1638=CARTESIAN_POINT('',(570.112537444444,361.197444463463,-809.365468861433));
#1639=CARTESIAN_POINT('',(571.54406192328,365.254155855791,-808.355214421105));
#1640=CARTESIAN_POINT('',(572.292377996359,367.264972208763,-807.825691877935));
#1641=CARTESIAN_POINT('',(573.85176958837,371.248693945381,-806.718699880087));
#1642=CARTESIAN_POINT('',(574.66284497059,373.221599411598,-806.141230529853));
#1643=CARTESIAN_POINT('',(576.345313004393,377.126976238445,-804.939220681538));
#1644=CARTESIAN_POINT('',(577.216706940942,379.059446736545,-804.314679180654));
#1645=CARTESIAN_POINT('',(579.017231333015,382.88157587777,-803.01947400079));
#1646=CARTESIAN_POINT('',(579.946362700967,384.771233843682,-802.34880959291));
#1647=CARTESIAN_POINT('',(581.907717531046,388.599317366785,-800.927554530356));
#1648=CARTESIAN_POINT('',(582.942774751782,390.535429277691,-800.17464170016));
#1649=CARTESIAN_POINT('',(585.07044576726,394.355831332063,-798.620253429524));
#1650=CARTESIAN_POINT('',(586.163060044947,396.2401210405,-797.818777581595));
#1651=CARTESIAN_POINT('',(588.402570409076,399.954861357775,-796.168543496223));
#1652=CARTESIAN_POINT('',(589.549464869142,401.785313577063,-795.319786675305));
#1653=CARTESIAN_POINT('',(591.89437841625,405.390879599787,-793.576196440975));
#1654=CARTESIAN_POINT('',(593.092401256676,407.165989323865,-792.681359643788));
#1655=CARTESIAN_POINT('',(595.536377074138,410.659542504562,-790.846861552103));
#1656=CARTESIAN_POINT('',(596.782336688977,412.377978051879,-789.907194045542));
#1657=CARTESIAN_POINT('',(599.318765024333,415.756762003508,-787.984486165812));
#1658=CARTESIAN_POINT('',(600.609234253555,417.417109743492,-787.001445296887));
#1659=CARTESIAN_POINT('',(603.231490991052,420.678845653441,-784.99330922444));
#1660=CARTESIAN_POINT('',(604.56328066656,422.280230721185,-783.968211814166));
#1661=CARTESIAN_POINT('',(607.264842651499,425.423159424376,-781.877438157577));
#1662=CARTESIAN_POINT('',(608.634613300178,426.96470566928,-780.811763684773));
#1663=CARTESIAN_POINT('',(611.580264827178,430.17406934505,-778.507221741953));
#1664=CARTESIAN_POINT('',(613.16072263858,431.833996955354,-777.263209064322));
#1665=CARTESIAN_POINT('',(616.361372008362,435.077416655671,-774.727583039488));
#1666=CARTESIAN_POINT('',(617.981564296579,436.660907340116,-773.435968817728));
#1667=CARTESIAN_POINT('',(621.257485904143,439.751333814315,-770.807074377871));
#1668=CARTESIAN_POINT('',(622.913214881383,441.258270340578,-769.469794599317));
#1669=CARTESIAN_POINT('',(626.256225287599,444.195806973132,-766.751449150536));
#1670=CARTESIAN_POINT('',(627.943508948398,445.626401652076,-765.370380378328));
#1671=CARTESIAN_POINT('',(633.048239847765,449.805301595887,-761.163162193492));
#1672=CARTESIAN_POINT('',(636.507580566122,452.439796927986,-758.273790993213));
#1673=CARTESIAN_POINT('',(643.508255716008,457.410114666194,-752.341798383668));
#1674=CARTESIAN_POINT('',(647.049600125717,459.745900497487,-749.299158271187));
#1675=CARTESIAN_POINT('',(653.352047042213,463.613744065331,-743.803912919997));
#1676=CARTESIAN_POINT('',(656.101590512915,465.205901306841,-741.380056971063));
#1677=CARTESIAN_POINT('',(661.623760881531,468.224679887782,-736.456164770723));
#1678=CARTESIAN_POINT('',(664.39638994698,469.651285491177,-733.956121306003));
#1679=CARTESIAN_POINT('',(669.956043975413,472.344158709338,-728.884807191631));
#1680=CARTESIAN_POINT('',(672.743073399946,473.610373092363,-726.313513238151));
#1681=CARTESIAN_POINT('',(678.322280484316,475.987211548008,-721.105710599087));
#1682=CARTESIAN_POINT('',(681.114458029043,477.097839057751,-718.469203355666));
#1683=CARTESIAN_POINT('',(686.700822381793,479.170598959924,-713.131774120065));
#1684=CARTESIAN_POINT('',(689.495005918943,480.132506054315,-710.430761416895));
#1685=CARTESIAN_POINT('',(695.074607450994,481.911449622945,-704.97270958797));
#1686=CARTESIAN_POINT('',(697.860025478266,482.728486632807,-702.2156706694));
#1687=CARTESIAN_POINT('',(703.416223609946,484.22330993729,-696.649896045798));
#1688=CARTESIAN_POINT('',(706.18700429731,484.901101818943,-693.841162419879));
#1689=CARTESIAN_POINT('',(711.709015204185,486.123070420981,-688.175797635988));
#1690=CARTESIAN_POINT('',(714.460244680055,486.667242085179,-685.319164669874));
#1691=CARTESIAN_POINT('',(721.079814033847,487.827428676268,-678.362423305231));
#1692=CARTESIAN_POINT('',(724.936131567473,488.378955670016,-674.239989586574));
#1693=CARTESIAN_POINT('',(732.589962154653,489.239856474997,-665.915854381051));
#1694=CARTESIAN_POINT('',(736.38747001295,489.549209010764,-661.714145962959));
#1695=CARTESIAN_POINT('',(743.9160797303,489.939986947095,-653.238857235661));
#1696=CARTESIAN_POINT('',(747.647158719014,490.021335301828,-648.965253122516));
#1697=CARTESIAN_POINT('',(755.03444779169,489.969202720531,-640.355494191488));
#1698=CARTESIAN_POINT('',(758.69065945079,489.835726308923,-636.019340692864));
#1699=CARTESIAN_POINT('',(765.931345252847,489.365746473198,-627.280996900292));
#1700=CARTESIAN_POINT('',(769.515626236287,489.02875671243,-622.87867312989));
#1701=CARTESIAN_POINT('',(776.598860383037,488.162778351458,-614.024716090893));
#1702=CARTESIAN_POINT('',(780.097813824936,487.633790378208,-609.573082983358));
#1703=CARTESIAN_POINT('',(787.006491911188,486.394299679,-600.626939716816));
#1704=CARTESIAN_POINT('',(790.416225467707,485.683815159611,-596.132433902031));
#1705=CARTESIAN_POINT('',(797.144227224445,484.090666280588,-587.105415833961));
#1706=CARTESIAN_POINT('',(800.462492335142,483.207996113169,-582.57290230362));
#1707=CARTESIAN_POINT('',(805.984306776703,481.579904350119,-574.894909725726));
#1708=CARTESIAN_POINT('',(808.212588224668,480.87760374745,-571.757958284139));
#1709=CARTESIAN_POINT('',(812.624304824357,479.39790926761,-565.470148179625));
#1710=CARTESIAN_POINT('',(814.807739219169,478.620514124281,-562.319289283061));
#1711=CARTESIAN_POINT('',(819.129382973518,476.992825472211,-556.00511835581));
#1712=CARTESIAN_POINT('',(821.267589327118,476.142527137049,-552.841805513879));
#1713=CARTESIAN_POINT('',(825.49825562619,474.37107709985,-546.504478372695));
#1714=CARTESIAN_POINT('',(827.590715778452,473.449925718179,-543.33046412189));
#1715=CARTESIAN_POINT('',(831.730723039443,471.538014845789,-536.971513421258));
#1716=CARTESIAN_POINT('',(833.778245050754,470.547217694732,-533.786571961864));
#1717=CARTESIAN_POINT('',(837.826953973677,468.497994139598,-527.409007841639));
#1718=CARTESIAN_POINT('',(839.828140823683,467.439567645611,-524.216385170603));
#1719=CARTESIAN_POINT('',(843.783902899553,465.256415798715,-517.825114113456));
#1720=CARTESIAN_POINT('',(845.738479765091,464.131692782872,-514.626465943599));
#1721=CARTESIAN_POINT('',(849.600921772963,461.816950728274,-508.224605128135));
#1722=CARTESIAN_POINT('',(851.50878694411,460.626931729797,-505.021392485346));
#1723=CARTESIAN_POINT('',(855.272710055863,458.185571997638,-498.620436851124));
#1724=CARTESIAN_POINT('',(857.128890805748,456.934400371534,-495.422701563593));
#1725=CARTESIAN_POINT('',(860.794496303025,454.368341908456,-489.025994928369));
#1726=CARTESIAN_POINT('',(862.603921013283,453.053455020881,-485.827023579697));
#1727=CARTESIAN_POINT('',(866.17596770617,450.360062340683,-479.429468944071));
#1728=CARTESIAN_POINT('',(867.938587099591,448.981553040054,-476.230885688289));
#1729=CARTESIAN_POINT('',(871.416756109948,446.160818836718,-469.836231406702));
#1730=CARTESIAN_POINT('',(873.132305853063,444.718594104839,-466.640160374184));
#1731=CARTESIAN_POINT('',(876.514934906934,441.770943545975,-460.254943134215));
#1732=CARTESIAN_POINT('',(878.182048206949,440.265563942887,-457.065793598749));
#1733=CARTESIAN_POINT('',(881.468875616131,437.189653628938,-450.694431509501));
#1734=CARTESIAN_POINT('',(883.088589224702,435.619122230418,-447.51221902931));
#1735=CARTESIAN_POINT('',(886.280068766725,432.411708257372,-441.157884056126));
#1736=CARTESIAN_POINT('',(887.851841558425,430.77483525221,-437.985760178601));
#1737=CARTESIAN_POINT('',(890.947250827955,427.432573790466,-431.654273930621));
#1738=CARTESIAN_POINT('',(892.470889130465,425.727187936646,-428.494911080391));
#1739=CARTESIAN_POINT('',(894.994814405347,422.796451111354,-423.190229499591));
#1740=CARTESIAN_POINT('',(896.00806068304,421.590076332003,-421.040569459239));
#1741=CARTESIAN_POINT('',(898.011621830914,419.143025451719,-416.750203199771));
#1742=CARTESIAN_POINT('',(899.001937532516,417.902350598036,-414.609496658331));
#1743=CARTESIAN_POINT('',(900.959358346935,415.385499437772,-410.338582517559));
#1744=CARTESIAN_POINT('',(901.926465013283,414.109325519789,-408.20837422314));
#1745=CARTESIAN_POINT('',(903.837248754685,411.519908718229,-403.959964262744));
#1746=CARTESIAN_POINT('',(904.780925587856,410.206665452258,-401.841762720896));
#1747=CARTESIAN_POINT('',(906.646060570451,407.539131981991,-397.615724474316));
#1748=CARTESIAN_POINT('',(907.567478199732,406.184775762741,-395.507911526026));
#1749=CARTESIAN_POINT('',(909.385981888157,403.435128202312,-391.308537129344));
#1750=CARTESIAN_POINT('',(910.283067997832,402.039836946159,-389.216975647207));
#1751=CARTESIAN_POINT('',(912.052321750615,399.206023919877,-385.052826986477));
#1752=CARTESIAN_POINT('',(912.924490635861,397.767504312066,-382.980238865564));
#1753=CARTESIAN_POINT('',(914.643287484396,394.844413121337,-378.85702484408));
#1754=CARTESIAN_POINT('',(915.489915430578,393.359841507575,-376.806398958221));
#1755=CARTESIAN_POINT('',(917.163754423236,390.328852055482,-372.713798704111));
#1756=CARTESIAN_POINT('',(917.990744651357,388.782021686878,-370.672039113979));
#1757=CARTESIAN_POINT('',(919.616867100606,385.63443535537,-366.619128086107));
#1758=CARTESIAN_POINT('',(920.415999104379,384.033678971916,-364.607976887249));
#1759=CARTESIAN_POINT('',(921.985507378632,380.772899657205,-360.620738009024));
#1760=CARTESIAN_POINT('',(922.755867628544,379.112844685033,-358.644670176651));
#1761=CARTESIAN_POINT('',(924.265684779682,375.729146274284,-354.735582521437));
#1762=CARTESIAN_POINT('',(925.00514225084,374.005504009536,-352.802561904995));
#1763=CARTESIAN_POINT('',(926.449001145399,370.493579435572,-348.993387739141));
#1764=CARTESIAN_POINT('',(927.153495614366,368.705493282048,-347.117089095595));
#1765=CARTESIAN_POINT('',(928.527014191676,365.05315109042,-343.426063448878));
#1766=CARTESIAN_POINT('',(929.196035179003,363.188888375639,-341.6113418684));
#1767=CARTESIAN_POINT('',(930.49433541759,359.378796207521,-338.058964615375));
#1768=CARTESIAN_POINT('',(931.123657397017,357.433058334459,-336.321226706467));
#1769=CARTESIAN_POINT('',(932.338693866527,353.450300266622,-332.938114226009));
#1770=CARTESIAN_POINT('',(932.924420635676,351.413306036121,-331.292713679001));
#1771=CARTESIAN_POINT('',(933.980645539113,347.484303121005,-328.302247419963));
#1772=CARTESIAN_POINT('',(934.456597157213,345.603369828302,-326.944606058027));
#1773=CARTESIAN_POINT('',(935.365024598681,341.75776616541,-324.336518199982));
#1774=CARTESIAN_POINT('',(935.79749724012,339.793089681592,-323.086079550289));
#1775=CARTESIAN_POINT('',(936.611788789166,335.780210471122,-320.717823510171));
#1776=CARTESIAN_POINT('',(936.993706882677,333.732181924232,-319.599746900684));
#1777=CARTESIAN_POINT('',(937.700274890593,329.548305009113,-317.520708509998));
#1778=CARTESIAN_POINT('',(938.024946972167,327.412491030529,-316.55968592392));
#1779=CARTESIAN_POINT('',(938.516079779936,323.747443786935,-315.099920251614));
#1780=CARTESIAN_POINT('',(938.700077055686,322.240400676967,-314.551177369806));
#1781=CARTESIAN_POINT('',(939.034578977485,319.190621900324,-313.551172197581));
#1782=CARTESIAN_POINT('',(939.185088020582,317.647890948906,-313.099897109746));
#1783=CARTESIAN_POINT('',(939.449857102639,314.532511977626,-312.304566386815));
#1784=CARTESIAN_POINT('',(939.564132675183,312.95987708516,-311.960464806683));
#1785=CARTESIAN_POINT('',(939.754188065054,309.791200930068,-311.387471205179));
#1786=CARTESIAN_POINT('',(939.829964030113,308.195157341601,-311.158590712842));
#1787=CARTESIAN_POINT('',(939.885615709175,306.59188491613,-310.990400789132));
#1788=B_SPLINE_CURVE_WITH_KNOTS('',3,(#1442,#1443,#1444,#1445,#1446,#1447,#1448,#1449,#1450,
#1451,#1452,#1453,#1454,#1455,#1456,#1457,#1458,#1459,#1460,#1461,#1462,#1463,#1464,#1465,#1466,
#1467,#1468,#1469,#1470,#1471,#1472,#1473,#1474,#1475,#1476,#1477,#1478,#1479,#1480,#1481,#1482,
#1483,#1484,#1485,#1486,#1487,#1488,#1489,#1490,#1491,#1492,#1493,#1494,#1495,#1496,#1497,#1498,
#1499,#1500,#1501,#1502,#1503,#1504,#1505,#1506,#1507,#1508,#1509,#1510,#1511,#1512,#1513,#1514,
#1515,#1516,#1517,#1518,#1519,#1520,#1521,#1522,#1523,#1524,#1525,#1526,#1527,#1528,#1529,#1530,
#1531,#1532,#1533,#1534,#1535,#1536,#1537,#1538,#1539,#1540,#1541,#1542,#1543,#1544,#1545,#1546,
#1547,#1548,#1549,#1550,#1551,#1552,#1553,#1554,#1555,#1556,#1557,#1558,#1559,#1560,#1561,#1562,
#1563,#1564,#1565,#1566,#1567,#1568,#1569,#1570,#1571,#1572,#1573,#1574,#1575,#1576,#1577,#1578,
#1579,#1580,#1581,#1582,#1583,#1584,#1585,#1586,#1587,#1588,#1589,#1590,#1591,#1592,#1593,#1594,
#1595,#1596,#1597,#1598,#1599,#1600,#1601,#1602,#1603,#1604,#1605,#1606,#1607,#1608,#1609,#1610,
#1611,#1612,#1613,#1614,#1615,#1616,#1617,#1618,#1619,#1620,#1621,#1622,#1623,#1624,#1625,#1626,
#1627,#1628,#1629,#1630,#1631,#1632,#1633,#1634,#1635,#1636,#1637,#1638,#1639,#1640,#1641,#1642,
#1643,#1644,#1645,#1646,#1647,#1648,#1649,#1650,#1651,#1652,#1653,#1654,#1655,#1656,#1657,#1658,
#1659,#1660,#1661,#1662,#1663,#1664,#1665,#1666,#1667,#1668,#1669,#1670,#1671,#1672,#1673,#1674,
#1675,#1676,#1677,#1678,#1679,#1680,#1681,#1682,#1683,#1684,#1685,#1686,#1687,#1688,#1689,#1690,
#1691,#1692,#1693,#1694,#1695,#1696,#1697,#1698,#1699,#1700,#1701,#1702,#1703,#1704,#1705,#1706,
#1707,#1708,#1709,#1710,#1711,#1712,#1713,#1714,#1715,#1716,#1717,#1718,#1719,#1720,#1721,#1722,
#1723,#1724,#1725,#1726,#1727,#1728,#1729,#1730,#1731,#1732,#1733,#1734,#1735,#1736,#1737,#1738,
#1739,#1740,#1741,#1742,#1743,#1744,#1745,#1746,#1747,#1748,#1749,#1750,#1751,#1752,#1753,#1754,
#1755,#1756,#1757,#1758,#1759,#1760,#1761,#1762,#1763,#1764,#1765,#1766,#1767,#1768,#1769,#1770,
#1771,#1772,#1773,#1774,#1775,#1776,#1777,#1778,#1779,#1780,#1781,#1782,#1783,#1784,#1785,#1786,
#1787),.UNSPECIFIED.,.T.,.F.,(4,2,2,2,2,2,2,2,2,2,2,2,2,2,2,2,2,2,2,2,2,2,2,2,2,2,2,2,2,2,2,2,2,
2,2,2,2,2,2,2,2,2,2,2,2,2,2,2,2,2,2,2,2,2,2,2,2,2,2,2,2,2,2,2,2,2,2,2,2,2,2,2,2,2,2,2,2,2,2,2,2,
2,2,2,2,2,2,2,2,2,2,2,2,2,2,2,2,2,2,2,2,2,2,2,2,2,2,2,2,2,2,2,2,2,2,2,2,2,2,2,2,2,2,2,2,2,2,2,2,
2,2,2,2,2,2,2,2,2,2,2,2,2,2,2,2,2,2,2,2,2,2,2,2,2,2,2,2,2,2,2,2,2,2,2,2,2,2,2,2,2,2,2,4),(0.,
5.54218418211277,11.084721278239,16.6306841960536,22.1768371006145,27.6757642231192,
33.1746670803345,38.6757124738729,44.1772901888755,49.3900146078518,54.6036994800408,
59.8210220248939,65.0380927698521,70.273647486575,75.5092108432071,80.7429645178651,
85.9768599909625,93.2508531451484,100.525563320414,107.803001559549,115.080228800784,
122.369252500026,129.658324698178,136.946156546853,144.233971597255,151.554328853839,
158.874688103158,166.195110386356,173.515644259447,188.144522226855,202.773812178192,
214.771126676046,226.768708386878,238.767359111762,250.765934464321,262.773490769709,
274.78106702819,286.788178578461,298.795280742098,310.765469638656,322.7356637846,
334.706332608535,346.676980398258,358.639967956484,370.603032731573,382.564994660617,
394.526667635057,410.091638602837,425.655933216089,441.220831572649,456.785845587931,
472.335473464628,487.885331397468,503.431535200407,518.976707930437,530.496286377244,
542.015502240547,553.534813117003,565.054175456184,576.562777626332,588.071529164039,
599.578050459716,611.083901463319,620.009556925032,628.934925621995,637.860002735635,
646.785130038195,655.703203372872,664.621097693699,673.538191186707,682.454950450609,
689.969865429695,697.48452716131,704.998699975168,712.512922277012,720.026462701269,
727.539986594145,735.053753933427,742.567531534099,750.121301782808,757.675081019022,
765.229073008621,772.783049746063,780.334951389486,787.886898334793,795.438251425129,
802.989427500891,809.816861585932,816.644156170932,823.471009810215,830.297897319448,
837.123013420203,843.948129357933,850.773246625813,857.598330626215,864.226437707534,
870.854507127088,877.482334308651,884.110175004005,890.738182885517,897.366176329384,
903.994311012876,910.622550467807,917.583516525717,924.544541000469,931.505357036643,
938.466684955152,945.428980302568,952.391355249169,959.354095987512,966.316532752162,
974.138071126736,981.959753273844,989.781360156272,997.603522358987,1013.25253620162,
1028.90346432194,1040.88805054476,1052.87377499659,1064.86346698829,1076.85289406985,
1088.86030974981,1100.86768103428,1112.87457044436,1124.88191412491,1141.89069319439,
1158.90096634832,1175.91698682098,1192.93264892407,1209.98913521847,1227.04556581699,
1244.10028609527,1261.15558172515,1272.88880437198,1284.62222488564,1296.35642278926,
1308.09056763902,1319.83110717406,1331.57166231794,1343.31180383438,1355.05193810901,
1366.76126529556,1378.47060178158,1390.18058466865,1401.89053616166,1413.59206160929,
1425.29371059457,1436.99367765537,1448.69320066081,1456.68836349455,1464.68323598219,
1472.67757181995,1480.67199015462,1488.68000565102,1496.68800451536,1504.69560347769,
1512.70320780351,1520.77759404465,1528.85204326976,1536.9309234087,1545.00965448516,
1553.06558575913,1561.12222463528,1569.17003872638,1577.2155774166,1584.31605608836,
1591.41705401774,1598.50390679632,1605.58800930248,1610.42786955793,1615.26709395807,
1620.10424092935,1624.94187180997),.UNSPECIFIED.);
#1789=CARTESIAN_POINT('',(939.885615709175,306.59188491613,-310.990400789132));
#1790=VERTEX_POINT('',#1789);
#1791=EDGE_CURVE('E313',#1790,#1790,#1788,.T.);
#1792=ORIENTED_EDGE('',*,*,#1791,.T.);
#1793=EDGE_LOOP('',(#1792));
#1794=FACE_BOUND('',#1793,.T.);
#1795=ADVANCED_FACE('F290',(#1419,#1430,#1441,#1794),#1066,.F.);
#1796=CARTESIAN_POINT('',(0.,990.,0.));
#1797=DIRECTION('',(0.,1.,0.));
#1798=DIRECTION('',(0.,0.,1.));
#1799=AXIS2_PLACEMENT_3D('',#1796,#1797,#1798);
#1800=PLANE('',#1799);
#1801=ORIENTED_EDGE('',*,*,#1427,.F.);
#1802=EDGE_LOOP('',(#1801));
#1803=FACE_BOUND('',#1802,.T.);
#1804=ADVANCED_FACE('F301',(#1803),#1800,.F.);
#1805=CARTESIAN_POINT('',(0.,10.,0.));
#1806=DIRECTION('',(0.,1.,0.));
#1807=DIRECTION('',(0.,0.,1.));
#1808=AXIS2_PLACEMENT_3D('',#1805,#1806,#1807);
#1809=PLANE('',#1808);
#1810=CARTESIAN_POINT('',(0.,10.,0.));
#1811=DIRECTION('',(0.,1.,0.));
#1812=DIRECTION('',(0.,0.,1.));
#1813=AXIS2_PLACEMENT_3D('',#1810,#1811,#1812);
#1814=CIRCLE('',#1813,190.);
#1815=CARTESIAN_POINT('',(0.,10.,190.));
#1816=VERTEX_POINT('',#1815);
#1817=EDGE_CURVE('E321',#1816,#1816,#1814,.F.);
#1818=ORIENTED_EDGE('',*,*,#1817,.T.);
#1819=EDGE_LOOP('',(#1818));
#1820=FACE_BOUND('',#1819,.T.);
#1821=ORIENTED_EDGE('',*,*,#1438,.T.);
#1822=EDGE_LOOP('',(#1821));
#1823=FACE_BOUND('',#1822,.T.);
#1824=ADVANCED_FACE('F297',(#1820,#1823),#1809,.T.);
#1825=CARTESIAN_POINT('',(-750.,650.,-1000.001));
#1826=DIRECTION('',(0.,0.,1.));
#1827=DIRECTION('',(1.,0.,0.));
#1828=AXIS2_PLACEMENT_3D('',#1825,#1826,#1827);
#1829=CYLINDRICAL_SURFACE('',#1828,190.);
#1830=ORIENTED_EDGE('',*,*,#954,.T.);
#1831=EDGE_LOOP('',(#1830));
#1832=FACE_BOUND('',#1831,.T.);
#1833=ORIENTED_EDGE('',*,*,#1416,.F.);
#1834=EDGE_LOOP('',(#1833));
#1835=FACE_BOUND('',#1834,.T.);
#1836=ADVANCED_FACE('F300',(#1832,#1835),#1829,.F.);
#1837=CARTESIAN_POINT('',(750.,300.,1600.001));
#1838=DIRECTION('',(0.,0.,-1.));
#1839=DIRECTION('',(-1.,0.,0.));
#1840=AXIS2_PLACEMENT_3D('',#1837,#1838,#1839);
#1841=CYLINDRICAL_SURFACE('',#1840,190.);
#1842=ORIENTED_EDGE('',*,*,#994,.F.);
#1843=EDGE_LOOP('',(#1842));
#1844=FACE_BOUND('',#1843,.T.);
#1845=ORIENTED_EDGE('',*,*,#1791,.F.);
#1846=EDGE_LOOP('',(#1845));
#1847=FACE_BOUND('',#1846,.T.);
#1848=ADVANCED_FACE('F295',(#1844,#1847),#1841,.F.);
#1849=CARTESIAN_POINT('',(0.,-1000.,0.));
#1850=DIRECTION('',(0.,1.,0.));
#1851=DIRECTION('',(0.,0.,1.));
#1852=AXIS2_PLACEMENT_3D('',#1849,#1850,#1851);
#1853=CYLINDRICAL_SURFACE('',#1852,190.);
#1854=ORIENTED_EDGE('',*,*,#1054,.T.);
#1855=EDGE_LOOP('',(#1854));
#1856=FACE_BOUND('',#1855,.T.);
#1857=ORIENTED_EDGE('',*,*,#1817,.F.);
#1858=EDGE_LOOP('',(#1857));
#1859=FACE_BOUND('',#1858,.T.);
#1860=ADVANCED_FACE('F292',(#1856,#1859),#1853,.F.);
#1861=CLOSED_SHELL('',(#912,#921,#941,#969,#981,#1009,#1021,#1041,#1061,#1795,#1804,#1824,#1836,
#1848,#1860));
#1862=MANIFOLD_SOLID_BREP('B101',#1861);
#1863=ADVANCED_BREP_SHAPE_REPRESENTATION('',(#18,#66,#114,#162,#1862),#14);
#1864=SHAPE_DEFINITION_REPRESENTATION(#9,#1863);
ENDSEC;
END-ISO-10303-21;
